VERSION 5.7 ;
  NOWIREEXTENSIONATPIN ON ;
  DIVIDERCHAR "/" ;
  BUSBITCHARS "[]" ;
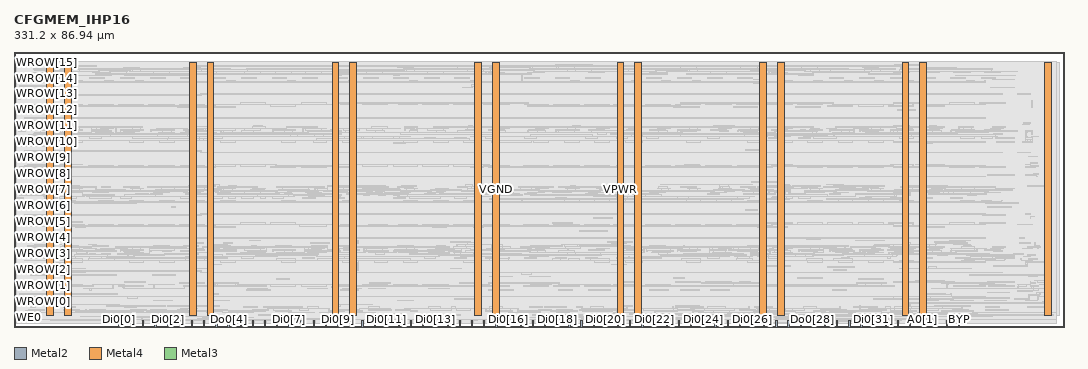
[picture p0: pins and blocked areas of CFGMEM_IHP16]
MACRO CFGMEM_IHP16
  CLASS BLOCK ;
  FOREIGN CFGMEM_IHP16 ;
  ORIGIN 0.000 0.000 ;
  SIZE 331.200 BY 86.940 ;
  PIN A0[0]
    DIRECTION INPUT ;
    USE SIGNAL ;
    ANTENNAGATEAREA 0.213200 ;
    ANTENNADIFFAREA 2.015400 ;
    PORT
      LAYER Metal2 ;
        RECT 282.520 0.000 282.920 2.000 ;
    END
  END A0[0]
  PIN A0[1]
    DIRECTION INPUT ;
    USE SIGNAL ;
    ANTENNAGATEAREA 0.213200 ;
    ANTENNADIFFAREA 2.015400 ;
    PORT
      LAYER Metal2 ;
        RECT 286.360 0.000 286.760 2.000 ;
    END
  END A0[1]
  PIN A0[2]
    DIRECTION INPUT ;
    USE SIGNAL ;
    ANTENNAGATEAREA 0.213200 ;
    ANTENNADIFFAREA 2.015400 ;
    PORT
      LAYER Metal2 ;
        RECT 290.200 0.000 290.600 2.000 ;
    END
  END A0[2]
  PIN A0[3]
    DIRECTION INPUT ;
    USE SIGNAL ;
    ANTENNAGATEAREA 0.213200 ;
    ANTENNADIFFAREA 2.015400 ;
    PORT
      LAYER Metal2 ;
        RECT 294.040 0.000 294.440 2.000 ;
    END
  END A0[3]
  PIN BYP
    DIRECTION INPUT ;
    USE SIGNAL ;
    ANTENNAGATEAREA 0.213200 ;
    ANTENNADIFFAREA 2.015400 ;
    PORT
      LAYER Metal2 ;
        RECT 297.880 0.000 298.280 2.000 ;
    END
  END BYP
  PIN Di0[0]
    DIRECTION INPUT ;
    USE SIGNAL ;
    ANTENNAGATEAREA 0.406900 ;
    ANTENNADIFFAREA 4.030800 ;
    PORT
      LAYER Metal2 ;
        RECT 32.920 0.000 33.320 2.000 ;
    END
  END Di0[0]
  PIN Di0[10]
    DIRECTION INPUT ;
    USE SIGNAL ;
    ANTENNAGATEAREA 0.406900 ;
    ANTENNADIFFAREA 4.030800 ;
    PORT
      LAYER Metal2 ;
        RECT 109.720 0.000 110.120 2.000 ;
    END
  END Di0[10]
  PIN Di0[11]
    DIRECTION INPUT ;
    USE SIGNAL ;
    ANTENNAGATEAREA 0.406900 ;
    ANTENNADIFFAREA 4.030800 ;
    PORT
      LAYER Metal2 ;
        RECT 117.400 0.000 117.800 2.000 ;
    END
  END Di0[11]
  PIN Di0[12]
    DIRECTION INPUT ;
    USE SIGNAL ;
    ANTENNAGATEAREA 0.406900 ;
    ANTENNADIFFAREA 4.030800 ;
    PORT
      LAYER Metal2 ;
        RECT 125.080 0.000 125.480 2.000 ;
    END
  END Di0[12]
  PIN Di0[13]
    DIRECTION INPUT ;
    USE SIGNAL ;
    ANTENNAGATEAREA 0.406900 ;
    ANTENNADIFFAREA 4.030800 ;
    PORT
      LAYER Metal2 ;
        RECT 132.760 0.000 133.160 2.000 ;
    END
  END Di0[13]
  PIN Di0[14]
    DIRECTION INPUT ;
    USE SIGNAL ;
    ANTENNAGATEAREA 0.406900 ;
    ANTENNADIFFAREA 4.030800 ;
    PORT
      LAYER Metal2 ;
        RECT 140.440 0.000 140.840 2.000 ;
    END
  END Di0[14]
  PIN Di0[15]
    DIRECTION INPUT ;
    USE SIGNAL ;
    ANTENNAGATEAREA 0.406900 ;
    ANTENNADIFFAREA 4.030800 ;
    PORT
      LAYER Metal2 ;
        RECT 148.120 0.000 148.520 2.000 ;
    END
  END Di0[15]
  PIN Di0[16]
    DIRECTION INPUT ;
    USE SIGNAL ;
    ANTENNAGATEAREA 0.406900 ;
    ANTENNADIFFAREA 4.030800 ;
    PORT
      LAYER Metal2 ;
        RECT 155.800 0.000 156.200 2.000 ;
    END
  END Di0[16]
  PIN Di0[17]
    DIRECTION INPUT ;
    USE SIGNAL ;
    ANTENNAGATEAREA 0.406900 ;
    ANTENNADIFFAREA 4.030800 ;
    PORT
      LAYER Metal2 ;
        RECT 163.480 0.000 163.880 2.000 ;
    END
  END Di0[17]
  PIN Di0[18]
    DIRECTION INPUT ;
    USE SIGNAL ;
    ANTENNAGATEAREA 0.406900 ;
    ANTENNADIFFAREA 4.030800 ;
    PORT
      LAYER Metal2 ;
        RECT 171.160 0.000 171.560 2.000 ;
    END
  END Di0[18]
  PIN Di0[19]
    DIRECTION INPUT ;
    USE SIGNAL ;
    ANTENNAGATEAREA 0.406900 ;
    ANTENNADIFFAREA 4.030800 ;
    PORT
      LAYER Metal2 ;
        RECT 178.840 0.000 179.240 2.000 ;
    END
  END Di0[19]
  PIN Di0[1]
    DIRECTION INPUT ;
    USE SIGNAL ;
    ANTENNAGATEAREA 0.406900 ;
    ANTENNADIFFAREA 4.030800 ;
    PORT
      LAYER Metal2 ;
        RECT 40.600 0.000 41.000 2.000 ;
    END
  END Di0[1]
  PIN Di0[20]
    DIRECTION INPUT ;
    USE SIGNAL ;
    ANTENNAGATEAREA 0.406900 ;
    ANTENNADIFFAREA 4.030800 ;
    PORT
      LAYER Metal2 ;
        RECT 186.520 0.000 186.920 2.000 ;
    END
  END Di0[20]
  PIN Di0[21]
    DIRECTION INPUT ;
    USE SIGNAL ;
    ANTENNAGATEAREA 0.406900 ;
    ANTENNADIFFAREA 4.030800 ;
    PORT
      LAYER Metal2 ;
        RECT 194.200 0.000 194.600 2.000 ;
    END
  END Di0[21]
  PIN Di0[22]
    DIRECTION INPUT ;
    USE SIGNAL ;
    ANTENNAGATEAREA 0.406900 ;
    ANTENNADIFFAREA 4.030800 ;
    PORT
      LAYER Metal2 ;
        RECT 201.880 0.000 202.280 2.000 ;
    END
  END Di0[22]
  PIN Di0[23]
    DIRECTION INPUT ;
    USE SIGNAL ;
    ANTENNAGATEAREA 0.406900 ;
    ANTENNADIFFAREA 4.030800 ;
    PORT
      LAYER Metal2 ;
        RECT 209.560 0.000 209.960 2.000 ;
    END
  END Di0[23]
  PIN Di0[24]
    DIRECTION INPUT ;
    USE SIGNAL ;
    ANTENNAGATEAREA 0.406900 ;
    ANTENNADIFFAREA 4.030800 ;
    PORT
      LAYER Metal2 ;
        RECT 217.240 0.000 217.640 2.000 ;
    END
  END Di0[24]
  PIN Di0[25]
    DIRECTION INPUT ;
    USE SIGNAL ;
    ANTENNAGATEAREA 0.406900 ;
    ANTENNADIFFAREA 4.030800 ;
    PORT
      LAYER Metal2 ;
        RECT 224.920 0.000 225.320 2.000 ;
    END
  END Di0[25]
  PIN Di0[26]
    DIRECTION INPUT ;
    USE SIGNAL ;
    ANTENNAGATEAREA 0.406900 ;
    ANTENNADIFFAREA 4.030800 ;
    PORT
      LAYER Metal2 ;
        RECT 232.600 0.000 233.000 2.000 ;
    END
  END Di0[26]
  PIN Di0[27]
    DIRECTION INPUT ;
    USE SIGNAL ;
    ANTENNAGATEAREA 0.406900 ;
    ANTENNADIFFAREA 4.030800 ;
    PORT
      LAYER Metal2 ;
        RECT 240.280 0.000 240.680 2.000 ;
    END
  END Di0[27]
  PIN Di0[28]
    DIRECTION INPUT ;
    USE SIGNAL ;
    ANTENNAGATEAREA 0.406900 ;
    ANTENNADIFFAREA 4.030800 ;
    PORT
      LAYER Metal2 ;
        RECT 247.960 0.000 248.360 2.000 ;
    END
  END Di0[28]
  PIN Di0[29]
    DIRECTION INPUT ;
    USE SIGNAL ;
    ANTENNAGATEAREA 0.406900 ;
    ANTENNADIFFAREA 4.030800 ;
    PORT
      LAYER Metal2 ;
        RECT 255.640 0.000 256.040 2.000 ;
    END
  END Di0[29]
  PIN Di0[2]
    DIRECTION INPUT ;
    USE SIGNAL ;
    ANTENNAGATEAREA 0.406900 ;
    ANTENNADIFFAREA 4.030800 ;
    PORT
      LAYER Metal2 ;
        RECT 48.280 0.000 48.680 2.000 ;
    END
  END Di0[2]
  PIN Di0[30]
    DIRECTION INPUT ;
    USE SIGNAL ;
    ANTENNAGATEAREA 0.406900 ;
    ANTENNADIFFAREA 4.030800 ;
    PORT
      LAYER Metal2 ;
        RECT 263.320 0.000 263.720 2.000 ;
    END
  END Di0[30]
  PIN Di0[31]
    DIRECTION INPUT ;
    USE SIGNAL ;
    ANTENNAGATEAREA 0.406900 ;
    ANTENNADIFFAREA 4.030800 ;
    PORT
      LAYER Metal2 ;
        RECT 271.000 0.000 271.400 2.000 ;
    END
  END Di0[31]
  PIN Di0[3]
    DIRECTION INPUT ;
    USE SIGNAL ;
    ANTENNAGATEAREA 0.406900 ;
    ANTENNADIFFAREA 4.030800 ;
    PORT
      LAYER Metal2 ;
        RECT 55.960 0.000 56.360 2.000 ;
    END
  END Di0[3]
  PIN Di0[4]
    DIRECTION INPUT ;
    USE SIGNAL ;
    ANTENNAGATEAREA 0.406900 ;
    ANTENNADIFFAREA 4.030800 ;
    PORT
      LAYER Metal2 ;
        RECT 63.640 0.000 64.040 2.000 ;
    END
  END Di0[4]
  PIN Di0[5]
    DIRECTION INPUT ;
    USE SIGNAL ;
    ANTENNAGATEAREA 0.406900 ;
    ANTENNADIFFAREA 4.030800 ;
    PORT
      LAYER Metal2 ;
        RECT 71.320 0.000 71.720 2.000 ;
    END
  END Di0[5]
  PIN Di0[6]
    DIRECTION INPUT ;
    USE SIGNAL ;
    ANTENNAGATEAREA 0.406900 ;
    ANTENNADIFFAREA 4.030800 ;
    PORT
      LAYER Metal2 ;
        RECT 79.000 0.000 79.400 2.000 ;
    END
  END Di0[6]
  PIN Di0[7]
    DIRECTION INPUT ;
    USE SIGNAL ;
    ANTENNAGATEAREA 0.406900 ;
    ANTENNADIFFAREA 4.030800 ;
    PORT
      LAYER Metal2 ;
        RECT 86.680 0.000 87.080 2.000 ;
    END
  END Di0[7]
  PIN Di0[8]
    DIRECTION INPUT ;
    USE SIGNAL ;
    ANTENNAGATEAREA 0.406900 ;
    ANTENNADIFFAREA 4.030800 ;
    PORT
      LAYER Metal2 ;
        RECT 94.360 0.000 94.760 2.000 ;
    END
  END Di0[8]
  PIN Di0[9]
    DIRECTION INPUT ;
    USE SIGNAL ;
    ANTENNAGATEAREA 0.406900 ;
    ANTENNADIFFAREA 4.030800 ;
    PORT
      LAYER Metal2 ;
        RECT 102.040 0.000 102.440 2.000 ;
    END
  END Di0[9]
  PIN Do0[0]
    DIRECTION OUTPUT ;
    USE SIGNAL ;
    ANTENNADIFFAREA 1.023000 ;
    PORT
      LAYER Metal2 ;
        RECT 36.760 0.000 37.160 2.000 ;
    END
  END Do0[0]
  PIN Do0[10]
    DIRECTION OUTPUT ;
    USE SIGNAL ;
    ANTENNADIFFAREA 1.023000 ;
    PORT
      LAYER Metal2 ;
        RECT 113.560 0.000 113.960 2.000 ;
    END
  END Do0[10]
  PIN Do0[11]
    DIRECTION OUTPUT ;
    USE SIGNAL ;
    ANTENNADIFFAREA 1.023000 ;
    PORT
      LAYER Metal2 ;
        RECT 121.240 0.000 121.640 2.000 ;
    END
  END Do0[11]
  PIN Do0[12]
    DIRECTION OUTPUT ;
    USE SIGNAL ;
    ANTENNADIFFAREA 1.023000 ;
    PORT
      LAYER Metal2 ;
        RECT 128.920 0.000 129.320 2.000 ;
    END
  END Do0[12]
  PIN Do0[13]
    DIRECTION OUTPUT ;
    USE SIGNAL ;
    ANTENNADIFFAREA 1.023000 ;
    PORT
      LAYER Metal2 ;
        RECT 136.600 0.000 137.000 2.000 ;
    END
  END Do0[13]
  PIN Do0[14]
    DIRECTION OUTPUT ;
    USE SIGNAL ;
    ANTENNADIFFAREA 1.023000 ;
    PORT
      LAYER Metal2 ;
        RECT 144.280 0.000 144.680 2.000 ;
    END
  END Do0[14]
  PIN Do0[15]
    DIRECTION OUTPUT ;
    USE SIGNAL ;
    ANTENNADIFFAREA 1.023000 ;
    PORT
      LAYER Metal2 ;
        RECT 151.960 0.000 152.360 2.000 ;
    END
  END Do0[15]
  PIN Do0[16]
    DIRECTION OUTPUT ;
    USE SIGNAL ;
    ANTENNADIFFAREA 1.023000 ;
    PORT
      LAYER Metal2 ;
        RECT 159.640 0.000 160.040 2.000 ;
    END
  END Do0[16]
  PIN Do0[17]
    DIRECTION OUTPUT ;
    USE SIGNAL ;
    ANTENNADIFFAREA 1.023000 ;
    PORT
      LAYER Metal2 ;
        RECT 167.320 0.000 167.720 2.000 ;
    END
  END Do0[17]
  PIN Do0[18]
    DIRECTION OUTPUT ;
    USE SIGNAL ;
    ANTENNADIFFAREA 1.023000 ;
    PORT
      LAYER Metal2 ;
        RECT 175.000 0.000 175.400 2.000 ;
    END
  END Do0[18]
  PIN Do0[19]
    DIRECTION OUTPUT ;
    USE SIGNAL ;
    ANTENNADIFFAREA 1.023000 ;
    PORT
      LAYER Metal2 ;
        RECT 182.680 0.000 183.080 2.000 ;
    END
  END Do0[19]
  PIN Do0[1]
    DIRECTION OUTPUT ;
    USE SIGNAL ;
    ANTENNADIFFAREA 1.023000 ;
    PORT
      LAYER Metal2 ;
        RECT 44.440 0.000 44.840 2.000 ;
    END
  END Do0[1]
  PIN Do0[20]
    DIRECTION OUTPUT ;
    USE SIGNAL ;
    ANTENNADIFFAREA 1.023000 ;
    PORT
      LAYER Metal2 ;
        RECT 190.360 0.000 190.760 2.000 ;
    END
  END Do0[20]
  PIN Do0[21]
    DIRECTION OUTPUT ;
    USE SIGNAL ;
    ANTENNADIFFAREA 1.023000 ;
    PORT
      LAYER Metal2 ;
        RECT 198.040 0.000 198.440 2.000 ;
    END
  END Do0[21]
  PIN Do0[22]
    DIRECTION OUTPUT ;
    USE SIGNAL ;
    ANTENNADIFFAREA 1.023000 ;
    PORT
      LAYER Metal2 ;
        RECT 205.720 0.000 206.120 2.000 ;
    END
  END Do0[22]
  PIN Do0[23]
    DIRECTION OUTPUT ;
    USE SIGNAL ;
    ANTENNADIFFAREA 1.023000 ;
    PORT
      LAYER Metal2 ;
        RECT 213.400 0.000 213.800 2.000 ;
    END
  END Do0[23]
  PIN Do0[24]
    DIRECTION OUTPUT ;
    USE SIGNAL ;
    ANTENNADIFFAREA 1.023000 ;
    PORT
      LAYER Metal2 ;
        RECT 221.080 0.000 221.480 2.000 ;
    END
  END Do0[24]
  PIN Do0[25]
    DIRECTION OUTPUT ;
    USE SIGNAL ;
    ANTENNADIFFAREA 1.023000 ;
    PORT
      LAYER Metal2 ;
        RECT 228.760 0.000 229.160 2.000 ;
    END
  END Do0[25]
  PIN Do0[26]
    DIRECTION OUTPUT ;
    USE SIGNAL ;
    ANTENNADIFFAREA 1.023000 ;
    PORT
      LAYER Metal2 ;
        RECT 236.440 0.000 236.840 2.000 ;
    END
  END Do0[26]
  PIN Do0[27]
    DIRECTION OUTPUT ;
    USE SIGNAL ;
    ANTENNADIFFAREA 1.023000 ;
    PORT
      LAYER Metal2 ;
        RECT 244.120 0.000 244.520 2.000 ;
    END
  END Do0[27]
  PIN Do0[28]
    DIRECTION OUTPUT ;
    USE SIGNAL ;
    ANTENNADIFFAREA 1.023000 ;
    PORT
      LAYER Metal2 ;
        RECT 251.800 0.000 252.200 2.000 ;
    END
  END Do0[28]
  PIN Do0[29]
    DIRECTION OUTPUT ;
    USE SIGNAL ;
    ANTENNADIFFAREA 1.023000 ;
    PORT
      LAYER Metal2 ;
        RECT 259.480 0.000 259.880 2.000 ;
    END
  END Do0[29]
  PIN Do0[2]
    DIRECTION OUTPUT ;
    USE SIGNAL ;
    ANTENNADIFFAREA 1.023000 ;
    PORT
      LAYER Metal2 ;
        RECT 52.120 0.000 52.520 2.000 ;
    END
  END Do0[2]
  PIN Do0[30]
    DIRECTION OUTPUT ;
    USE SIGNAL ;
    ANTENNADIFFAREA 1.023000 ;
    PORT
      LAYER Metal2 ;
        RECT 267.160 0.000 267.560 2.000 ;
    END
  END Do0[30]
  PIN Do0[31]
    DIRECTION OUTPUT ;
    USE SIGNAL ;
    ANTENNADIFFAREA 1.023000 ;
    PORT
      LAYER Metal2 ;
        RECT 274.840 0.000 275.240 2.000 ;
    END
  END Do0[31]
  PIN Do0[3]
    DIRECTION OUTPUT ;
    USE SIGNAL ;
    ANTENNADIFFAREA 1.023000 ;
    PORT
      LAYER Metal2 ;
        RECT 59.800 0.000 60.200 2.000 ;
    END
  END Do0[3]
  PIN Do0[4]
    DIRECTION OUTPUT ;
    USE SIGNAL ;
    ANTENNADIFFAREA 1.023000 ;
    PORT
      LAYER Metal2 ;
        RECT 67.480 0.000 67.880 2.000 ;
    END
  END Do0[4]
  PIN Do0[5]
    DIRECTION OUTPUT ;
    USE SIGNAL ;
    ANTENNADIFFAREA 1.023000 ;
    PORT
      LAYER Metal2 ;
        RECT 75.160 0.000 75.560 2.000 ;
    END
  END Do0[5]
  PIN Do0[6]
    DIRECTION OUTPUT ;
    USE SIGNAL ;
    ANTENNADIFFAREA 1.023000 ;
    PORT
      LAYER Metal2 ;
        RECT 82.840 0.000 83.240 2.000 ;
    END
  END Do0[6]
  PIN Do0[7]
    DIRECTION OUTPUT ;
    USE SIGNAL ;
    ANTENNADIFFAREA 1.023000 ;
    PORT
      LAYER Metal2 ;
        RECT 90.520 0.000 90.920 2.000 ;
    END
  END Do0[7]
  PIN Do0[8]
    DIRECTION OUTPUT ;
    USE SIGNAL ;
    ANTENNADIFFAREA 1.023000 ;
    PORT
      LAYER Metal2 ;
        RECT 98.200 0.000 98.600 2.000 ;
    END
  END Do0[8]
  PIN Do0[9]
    DIRECTION OUTPUT ;
    USE SIGNAL ;
    ANTENNADIFFAREA 1.023000 ;
    PORT
      LAYER Metal2 ;
        RECT 105.880 0.000 106.280 2.000 ;
    END
  END Do0[9]
  PIN EN0
    DIRECTION INPUT ;
    USE SIGNAL ;
    ANTENNAGATEAREA 0.373100 ;
    ANTENNADIFFAREA 4.030800 ;
    PORT
      LAYER Metal2 ;
        RECT 278.680 0.000 279.080 2.000 ;
    END
  END EN0
  PIN VGND
    DIRECTION INOUT ;
    USE GROUND ;
    PORT
      LAYER Metal4 ;
        RECT 16.010 3.560 18.110 83.380 ;
    END
    PORT
      LAYER Metal4 ;
        RECT 60.970 3.560 63.070 83.380 ;
    END
    PORT
      LAYER Metal4 ;
        RECT 105.930 3.560 108.030 83.380 ;
    END
    PORT
      LAYER Metal4 ;
        RECT 150.890 3.560 152.990 83.380 ;
    END
    PORT
      LAYER Metal4 ;
        RECT 195.850 3.560 197.950 83.380 ;
    END
    PORT
      LAYER Metal4 ;
        RECT 240.810 3.560 242.910 83.380 ;
    END
    PORT
      LAYER Metal4 ;
        RECT 285.770 3.560 287.870 83.380 ;
    END
  END VGND
  PIN VPWR
    DIRECTION INOUT ;
    USE POWER ;
    PORT
      LAYER Metal4 ;
        RECT 10.390 3.560 12.490 83.380 ;
    END
    PORT
      LAYER Metal4 ;
        RECT 55.350 3.560 57.450 83.380 ;
    END
    PORT
      LAYER Metal4 ;
        RECT 100.310 3.560 102.410 83.380 ;
    END
    PORT
      LAYER Metal4 ;
        RECT 145.270 3.560 147.370 83.380 ;
    END
    PORT
      LAYER Metal4 ;
        RECT 190.230 3.560 192.330 83.380 ;
    END
    PORT
      LAYER Metal4 ;
        RECT 235.190 3.560 237.290 83.380 ;
    END
    PORT
      LAYER Metal4 ;
        RECT 280.150 3.560 282.250 83.380 ;
    END
    PORT
      LAYER Metal4 ;
        RECT 325.110 3.560 327.210 83.380 ;
    END
  END VPWR
  PIN WE0
    DIRECTION INPUT ;
    USE SIGNAL ;
    ANTENNAGATEAREA 3.078400 ;
    ANTENNADIFFAREA 32.246399 ;
    PORT
      LAYER Metal3 ;
        RECT 0.000 2.740 2.000 3.140 ;
    END
  END WE0
  PIN WROW[0]
    DIRECTION INPUT ;
    USE SIGNAL ;
    ANTENNAGATEAREA 0.192400 ;
    ANTENNADIFFAREA 2.015400 ;
    PORT
      LAYER Metal3 ;
        RECT 0.000 7.780 2.000 8.180 ;
    END
  END WROW[0]
  PIN WROW[10]
    DIRECTION INPUT ;
    USE SIGNAL ;
    ANTENNAGATEAREA 0.192400 ;
    ANTENNADIFFAREA 2.015400 ;
    PORT
      LAYER Metal3 ;
        RECT 0.000 58.180 2.000 58.580 ;
    END
  END WROW[10]
  PIN WROW[11]
    DIRECTION INPUT ;
    USE SIGNAL ;
    ANTENNAGATEAREA 0.192400 ;
    ANTENNADIFFAREA 2.015400 ;
    PORT
      LAYER Metal3 ;
        RECT 0.000 63.220 2.000 63.620 ;
    END
  END WROW[11]
  PIN WROW[12]
    DIRECTION INPUT ;
    USE SIGNAL ;
    ANTENNAGATEAREA 0.192400 ;
    ANTENNADIFFAREA 2.015400 ;
    PORT
      LAYER Metal3 ;
        RECT 0.000 68.260 2.000 68.660 ;
    END
  END WROW[12]
  PIN WROW[13]
    DIRECTION INPUT ;
    USE SIGNAL ;
    ANTENNAGATEAREA 0.192400 ;
    ANTENNADIFFAREA 2.015400 ;
    PORT
      LAYER Metal3 ;
        RECT 0.000 73.300 2.000 73.700 ;
    END
  END WROW[13]
  PIN WROW[14]
    DIRECTION INPUT ;
    USE SIGNAL ;
    ANTENNAGATEAREA 0.192400 ;
    ANTENNADIFFAREA 2.015400 ;
    PORT
      LAYER Metal3 ;
        RECT 0.000 78.340 2.000 78.740 ;
    END
  END WROW[14]
  PIN WROW[15]
    DIRECTION INPUT ;
    USE SIGNAL ;
    ANTENNAGATEAREA 0.192400 ;
    ANTENNADIFFAREA 2.015400 ;
    PORT
      LAYER Metal3 ;
        RECT 0.000 83.380 2.000 83.780 ;
    END
  END WROW[15]
  PIN WROW[1]
    DIRECTION INPUT ;
    USE SIGNAL ;
    ANTENNAGATEAREA 0.192400 ;
    ANTENNADIFFAREA 2.015400 ;
    PORT
      LAYER Metal3 ;
        RECT 0.000 12.820 2.000 13.220 ;
    END
  END WROW[1]
  PIN WROW[2]
    DIRECTION INPUT ;
    USE SIGNAL ;
    ANTENNAGATEAREA 0.192400 ;
    ANTENNADIFFAREA 2.015400 ;
    PORT
      LAYER Metal3 ;
        RECT 0.000 17.860 2.000 18.260 ;
    END
  END WROW[2]
  PIN WROW[3]
    DIRECTION INPUT ;
    USE SIGNAL ;
    ANTENNAGATEAREA 0.192400 ;
    ANTENNADIFFAREA 2.015400 ;
    PORT
      LAYER Metal3 ;
        RECT 0.000 22.900 2.000 23.300 ;
    END
  END WROW[3]
  PIN WROW[4]
    DIRECTION INPUT ;
    USE SIGNAL ;
    ANTENNAGATEAREA 0.192400 ;
    ANTENNADIFFAREA 2.015400 ;
    PORT
      LAYER Metal3 ;
        RECT 0.000 27.940 2.000 28.340 ;
    END
  END WROW[4]
  PIN WROW[5]
    DIRECTION INPUT ;
    USE SIGNAL ;
    ANTENNAGATEAREA 0.192400 ;
    ANTENNADIFFAREA 2.015400 ;
    PORT
      LAYER Metal3 ;
        RECT 0.000 32.980 2.000 33.380 ;
    END
  END WROW[5]
  PIN WROW[6]
    DIRECTION INPUT ;
    USE SIGNAL ;
    ANTENNAGATEAREA 0.192400 ;
    ANTENNADIFFAREA 2.015400 ;
    PORT
      LAYER Metal3 ;
        RECT 0.000 38.020 2.000 38.420 ;
    END
  END WROW[6]
  PIN WROW[7]
    DIRECTION INPUT ;
    USE SIGNAL ;
    ANTENNAGATEAREA 0.192400 ;
    ANTENNADIFFAREA 2.015400 ;
    PORT
      LAYER Metal3 ;
        RECT 0.000 43.060 2.000 43.460 ;
    END
  END WROW[7]
  PIN WROW[8]
    DIRECTION INPUT ;
    USE SIGNAL ;
    ANTENNAGATEAREA 0.192400 ;
    ANTENNADIFFAREA 2.015400 ;
    PORT
      LAYER Metal3 ;
        RECT 0.000 48.100 2.000 48.500 ;
    END
  END WROW[8]
  PIN WROW[9]
    DIRECTION INPUT ;
    USE SIGNAL ;
    ANTENNAGATEAREA 0.192400 ;
    ANTENNADIFFAREA 2.015400 ;
    PORT
      LAYER Metal3 ;
        RECT 0.000 53.140 2.000 53.540 ;
    END
  END WROW[9]
  OBS
      LAYER GatPoly ;
        RECT 1.440 3.630 329.760 83.310 ;
      LAYER Metal1 ;
        RECT 1.440 3.560 329.760 83.380 ;
      LAYER Metal2 ;
        RECT 0.855 2.210 328.905 83.725 ;
        RECT 0.855 1.115 32.710 2.210 ;
        RECT 33.530 1.115 36.550 2.210 ;
        RECT 37.370 1.115 40.390 2.210 ;
        RECT 41.210 1.115 44.230 2.210 ;
        RECT 45.050 1.115 48.070 2.210 ;
        RECT 48.890 1.115 51.910 2.210 ;
        RECT 52.730 1.115 55.750 2.210 ;
        RECT 56.570 1.115 59.590 2.210 ;
        RECT 60.410 1.115 63.430 2.210 ;
        RECT 64.250 1.115 67.270 2.210 ;
        RECT 68.090 1.115 71.110 2.210 ;
        RECT 71.930 1.115 74.950 2.210 ;
        RECT 75.770 1.115 78.790 2.210 ;
        RECT 79.610 1.115 82.630 2.210 ;
        RECT 83.450 1.115 86.470 2.210 ;
        RECT 87.290 1.115 90.310 2.210 ;
        RECT 91.130 1.115 94.150 2.210 ;
        RECT 94.970 1.115 97.990 2.210 ;
        RECT 98.810 1.115 101.830 2.210 ;
        RECT 102.650 1.115 105.670 2.210 ;
        RECT 106.490 1.115 109.510 2.210 ;
        RECT 110.330 1.115 113.350 2.210 ;
        RECT 114.170 1.115 117.190 2.210 ;
        RECT 118.010 1.115 121.030 2.210 ;
        RECT 121.850 1.115 124.870 2.210 ;
        RECT 125.690 1.115 128.710 2.210 ;
        RECT 129.530 1.115 132.550 2.210 ;
        RECT 133.370 1.115 136.390 2.210 ;
        RECT 137.210 1.115 140.230 2.210 ;
        RECT 141.050 1.115 144.070 2.210 ;
        RECT 144.890 1.115 147.910 2.210 ;
        RECT 148.730 1.115 151.750 2.210 ;
        RECT 152.570 1.115 155.590 2.210 ;
        RECT 156.410 1.115 159.430 2.210 ;
        RECT 160.250 1.115 163.270 2.210 ;
        RECT 164.090 1.115 167.110 2.210 ;
        RECT 167.930 1.115 170.950 2.210 ;
        RECT 171.770 1.115 174.790 2.210 ;
        RECT 175.610 1.115 178.630 2.210 ;
        RECT 179.450 1.115 182.470 2.210 ;
        RECT 183.290 1.115 186.310 2.210 ;
        RECT 187.130 1.115 190.150 2.210 ;
        RECT 190.970 1.115 193.990 2.210 ;
        RECT 194.810 1.115 197.830 2.210 ;
        RECT 198.650 1.115 201.670 2.210 ;
        RECT 202.490 1.115 205.510 2.210 ;
        RECT 206.330 1.115 209.350 2.210 ;
        RECT 210.170 1.115 213.190 2.210 ;
        RECT 214.010 1.115 217.030 2.210 ;
        RECT 217.850 1.115 220.870 2.210 ;
        RECT 221.690 1.115 224.710 2.210 ;
        RECT 225.530 1.115 228.550 2.210 ;
        RECT 229.370 1.115 232.390 2.210 ;
        RECT 233.210 1.115 236.230 2.210 ;
        RECT 237.050 1.115 240.070 2.210 ;
        RECT 240.890 1.115 243.910 2.210 ;
        RECT 244.730 1.115 247.750 2.210 ;
        RECT 248.570 1.115 251.590 2.210 ;
        RECT 252.410 1.115 255.430 2.210 ;
        RECT 256.250 1.115 259.270 2.210 ;
        RECT 260.090 1.115 263.110 2.210 ;
        RECT 263.930 1.115 266.950 2.210 ;
        RECT 267.770 1.115 270.790 2.210 ;
        RECT 271.610 1.115 274.630 2.210 ;
        RECT 275.450 1.115 278.470 2.210 ;
        RECT 279.290 1.115 282.310 2.210 ;
        RECT 283.130 1.115 286.150 2.210 ;
        RECT 286.970 1.115 289.990 2.210 ;
        RECT 290.810 1.115 293.830 2.210 ;
        RECT 294.650 1.115 297.670 2.210 ;
        RECT 298.490 1.115 328.905 2.210 ;
     LAYER Metal3 ;
        RECT 159.695 2.840 164.785 3.040 ;
        RECT 155.855 4.520 166.180 4.720 ;
        RECT 155.855 4.720 157.105 4.940 ;
        RECT 158.735 4.720 166.180 4.940 ;
        RECT 171.215 4.520 175.345 4.940 ;
        RECT 148.700 4.940 157.105 5.140 ;
        RECT 158.735 4.940 166.225 5.140 ;
        RECT 169.340 4.940 177.745 5.140 ;
        RECT 148.700 5.140 148.945 5.360 ;
        RECT 165.500 5.140 166.225 5.360 ;
        RECT 169.340 5.140 169.585 5.360 ;
        RECT 120.335 5.360 124.945 5.560 ;
        RECT 165.500 5.360 169.585 5.560 ;
        RECT 171.215 5.140 176.305 5.560 ;
        RECT 123.215 5.560 124.945 5.780 ;
        RECT 131.375 5.360 137.905 5.780 ;
        RECT 139.535 5.360 144.145 5.780 ;
        RECT 148.655 5.360 148.945 5.780 ;
        RECT 150.095 5.140 156.625 5.780 ;
        RECT 158.780 5.140 158.980 5.780 ;
        RECT 123.215 5.780 158.980 5.980 ;
        RECT 130.895 5.980 134.545 6.400 ;
        RECT 138.095 5.980 139.345 6.400 ;
        RECT 150.095 5.980 154.225 6.400 ;
        RECT 162.575 6.200 166.705 6.400 ;
        RECT 232.700 1.160 255.025 1.360 ;
        RECT 248.060 1.360 255.025 1.580 ;
        RECT 248.060 1.580 274.225 1.780 ;
        RECT 232.700 1.360 232.900 2.000 ;
        RECT 248.060 1.780 248.305 2.000 ;
        RECT 251.855 1.780 274.225 2.000 ;
        RECT 232.655 2.000 232.945 2.200 ;
        RECT 186.575 2.000 198.820 2.200 ;
        RECT 186.575 2.200 189.265 2.420 ;
        RECT 198.575 2.200 198.820 2.420 ;
        RECT 248.015 2.000 248.305 2.420 ;
        RECT 251.855 2.000 279.985 2.420 ;
        RECT 178.895 2.420 189.265 2.620 ;
        RECT 205.775 2.420 222.385 2.620 ;
        RECT 240.335 2.420 289.585 2.620 ;
        RECT 178.895 2.620 183.985 2.840 ;
        RECT 198.575 2.420 198.865 2.840 ;
        RECT 205.775 2.620 212.785 2.840 ;
        RECT 240.335 2.620 251.185 2.840 ;
        RECT 175.055 2.840 183.985 3.040 ;
        RECT 198.095 2.840 212.785 3.040 ;
        RECT 251.900 2.620 254.545 3.040 ;
        RECT 175.055 3.040 179.665 3.260 ;
        RECT 198.095 3.040 203.185 3.260 ;
        RECT 228.815 2.840 251.185 3.260 ;
        RECT 251.900 3.040 252.100 3.260 ;
        RECT 259.100 2.620 265.105 3.260 ;
        RECT 267.215 2.620 269.905 3.260 ;
        RECT 171.215 3.260 179.665 3.460 ;
        RECT 190.415 3.260 203.185 3.460 ;
        RECT 217.295 3.260 252.100 3.460 ;
        RECT 255.695 3.260 308.785 3.460 ;
        RECT 171.215 3.460 179.185 3.680 ;
        RECT 199.535 3.460 203.185 3.680 ;
        RECT 217.295 3.460 233.425 3.680 ;
        RECT 244.175 3.460 252.100 3.680 ;
        RECT 255.695 3.460 270.385 3.680 ;
        RECT 297.935 3.460 308.785 3.680 ;
        RECT 163.535 3.680 179.185 3.880 ;
        RECT 297.935 3.680 327.985 3.880 ;
        RECT 209.615 3.680 233.425 3.880 ;
        RECT 244.175 3.680 270.385 3.880 ;
        RECT 195.935 3.460 197.865 4.100 ;
        RECT 199.535 3.680 205.105 4.100 ;
        RECT 209.615 3.880 214.180 4.100 ;
        RECT 224.975 3.880 233.425 4.100 ;
        RECT 235.055 3.460 235.345 4.100 ;
        RECT 240.895 3.460 242.825 4.100 ;
        RECT 244.175 3.880 246.865 4.100 ;
        RECT 263.375 3.880 270.385 4.100 ;
        RECT 274.460 3.460 285.265 4.100 ;
        RECT 285.855 3.460 287.785 4.100 ;
        RECT 297.935 3.880 303.985 4.100 ;
        RECT 187.535 4.100 192.145 4.300 ;
        RECT 194.255 4.100 214.180 4.300 ;
        RECT 224.975 4.100 246.865 4.300 ;
        RECT 263.375 4.100 303.985 4.300 ;
        RECT 188.975 4.300 192.145 4.520 ;
        RECT 194.255 4.300 198.385 4.520 ;
        RECT 224.975 4.300 241.585 4.520 ;
        RECT 246.620 4.300 246.865 4.520 ;
        RECT 263.375 4.300 265.585 4.520 ;
        RECT 302.255 4.300 303.985 4.520 ;
        RECT 188.975 4.520 198.385 4.720 ;
        RECT 201.935 4.300 202.225 4.720 ;
        RECT 246.620 4.520 252.580 4.720 ;
        RECT 284.975 4.300 294.385 4.720 ;
        RECT 302.255 4.520 328.945 4.720 ;
        RECT 215.855 4.520 241.585 4.720 ;
        RECT 254.735 4.520 265.585 4.720 ;
        RECT 273.500 4.300 283.345 4.720 ;
        RECT 201.980 4.720 202.225 4.940 ;
        RECT 213.980 4.300 214.180 4.940 ;
        RECT 215.855 4.720 217.585 4.940 ;
        RECT 233.135 4.720 241.585 4.940 ;
        RECT 252.335 4.720 252.580 4.940 ;
        RECT 254.735 4.720 255.985 4.940 ;
        RECT 257.180 4.720 265.585 4.940 ;
        RECT 273.500 4.720 273.745 4.940 ;
        RECT 276.380 4.720 283.345 4.940 ;
        RECT 292.655 4.720 294.385 4.940 ;
        RECT 302.255 4.720 302.500 4.940 ;
        RECT 213.935 4.940 217.585 5.140 ;
        RECT 252.335 4.940 255.985 5.140 ;
        RECT 276.380 4.940 284.785 5.140 ;
        RECT 292.655 4.940 302.500 5.140 ;
        RECT 189.980 4.720 196.900 5.140 ;
        RECT 201.980 4.940 209.380 5.140 ;
        RECT 233.135 4.940 246.385 5.140 ;
        RECT 257.180 4.940 273.745 5.140 ;
        RECT 179.375 4.940 188.785 5.360 ;
        RECT 189.980 5.140 195.505 5.360 ;
        RECT 196.655 5.140 196.900 5.360 ;
        RECT 201.980 5.140 207.985 5.360 ;
        RECT 209.180 5.140 209.380 5.360 ;
        RECT 213.935 5.140 214.705 5.360 ;
        RECT 220.700 4.720 225.745 5.360 ;
        RECT 233.135 5.140 233.905 5.360 ;
        RECT 245.615 5.140 246.385 5.360 ;
        RECT 254.255 5.140 255.985 5.360 ;
        RECT 257.180 5.140 262.705 5.360 ;
        RECT 266.780 5.140 273.745 5.360 ;
        RECT 276.380 5.140 276.625 5.360 ;
        RECT 178.415 5.360 195.505 5.560 ;
        RECT 196.655 5.360 196.945 5.560 ;
        RECT 228.815 5.360 233.905 5.560 ;
        RECT 254.255 5.360 262.705 5.560 ;
        RECT 296.015 5.140 301.105 5.560 ;
        RECT 209.180 5.360 214.705 5.560 ;
        RECT 234.575 5.140 237.220 5.560 ;
        RECT 266.780 5.360 275.185 5.560 ;
        RECT 196.700 5.560 196.945 5.780 ;
        RECT 198.575 5.360 207.985 5.780 ;
        RECT 209.180 5.560 209.380 5.780 ;
        RECT 213.455 5.560 214.705 5.780 ;
        RECT 217.775 5.360 227.185 5.780 ;
        RECT 228.815 5.560 231.940 5.780 ;
        RECT 234.575 5.560 235.345 5.780 ;
        RECT 236.975 5.560 237.220 5.780 ;
        RECT 238.415 5.140 243.505 5.780 ;
        RECT 245.615 5.360 249.265 5.780 ;
        RECT 254.255 5.560 260.740 5.780 ;
        RECT 269.615 5.560 275.185 5.780 ;
        RECT 276.335 5.360 276.625 5.780 ;
        RECT 277.775 5.140 282.865 5.780 ;
        RECT 286.415 5.360 291.505 5.780 ;
        RECT 296.015 5.560 299.140 5.780 ;
        RECT 196.700 5.780 209.380 5.980 ;
        RECT 178.940 5.560 193.540 5.980 ;
        RECT 213.455 5.780 231.940 5.980 ;
        RECT 236.975 5.780 260.740 5.980 ;
        RECT 269.615 5.780 299.140 5.980 ;
        RECT 178.940 5.980 179.185 6.200 ;
        RECT 193.295 5.980 193.540 6.200 ;
        RECT 208.700 5.980 209.380 6.200 ;
        RECT 213.455 5.980 217.585 6.200 ;
        RECT 231.695 5.980 231.940 6.200 ;
        RECT 234.095 5.780 235.345 6.200 ;
        RECT 236.975 5.980 239.185 6.200 ;
        RECT 260.495 5.980 260.740 6.200 ;
        RECT 266.780 5.560 266.980 6.200 ;
        RECT 269.615 5.980 272.305 6.200 ;
        RECT 298.895 5.980 299.140 6.200 ;
        RECT 177.455 6.200 179.185 6.400 ;
        RECT 181.775 5.980 185.905 6.400 ;
        RECT 207.695 5.980 207.985 6.400 ;
        RECT 208.700 6.200 217.585 6.400 ;
        RECT 218.735 5.980 224.305 6.400 ;
        RECT 231.695 6.200 231.985 6.400 ;
        RECT 233.615 6.200 239.185 6.400 ;
        RECT 248.975 5.980 253.105 6.400 ;
        RECT 260.495 6.200 260.785 6.400 ;
        RECT 264.815 6.200 272.305 6.400 ;
        RECT 274.895 5.980 276.625 6.400 ;
        RECT 277.775 5.980 281.905 6.400 ;
        RECT 283.055 5.980 292.945 6.400 ;
        RECT 193.295 6.200 193.585 6.620 ;
        RECT 290.255 6.400 292.945 6.620 ;
        RECT 298.895 6.200 299.185 6.620 ;
        RECT 190.895 6.620 195.025 6.820 ;
        RECT 208.700 6.400 216.145 6.820 ;
        RECT 266.735 6.400 267.025 6.820 ;
        RECT 290.255 6.620 301.585 6.820 ;
        RECT 295.535 8.300 302.545 8.500 ;
        RECT 287.855 8.300 291.505 8.720 ;
        RECT 295.535 8.500 296.260 8.720 ;
        RECT 271.055 8.720 296.260 8.920 ;
        RECT 296.060 8.920 296.260 9.140 ;
        RECT 296.060 9.140 314.065 9.340 ;
        RECT 35.855 9.140 39.025 9.560 ;
        RECT 277.295 8.920 289.105 9.560 ;
        RECT 296.060 9.340 306.385 9.560 ;
        RECT 3.215 9.560 306.385 9.760 ;
        RECT 286.895 9.760 295.780 10.180 ;
        RECT 286.895 10.180 293.905 10.400 ;
        RECT 295.535 10.180 295.780 10.400 ;
        RECT 286.415 10.400 293.905 10.600 ;
        RECT 295.535 10.400 295.825 10.600 ;
        RECT 23.855 11.660 24.300 12.080 ;
        RECT 1.775 12.080 2.500 12.280 ;
        RECT 4.175 12.080 12.100 12.280 ;
        RECT 21.935 12.080 31.300 12.280 ;
        RECT 34.460 12.080 53.860 12.280 ;
        RECT 34.460 12.280 34.705 12.500 ;
        RECT 100.175 12.500 101.425 12.700 ;
        RECT 2.300 12.280 2.500 12.820 ;
        RECT 2.000 12.820 2.500 12.920 ;
        RECT 11.900 12.280 12.100 12.920 ;
        RECT 31.100 12.280 31.300 12.920 ;
        RECT 34.260 12.500 34.705 12.920 ;
        RECT 44.060 12.280 44.260 12.920 ;
        RECT 53.660 12.280 53.860 12.920 ;
        RECT 56.540 12.500 57.220 12.920 ;
        RECT 100.700 12.700 101.425 12.920 ;
        RECT 32.975 12.920 40.945 13.120 ;
        RECT 53.615 12.920 79.780 13.120 ;
        RECT 100.700 12.920 156.145 13.120 ;
        RECT 160.655 12.920 168.625 13.120 ;
        RECT 170.255 12.920 178.225 13.120 ;
        RECT 179.855 12.920 277.585 13.120 ;
        RECT 2.000 12.920 5.425 13.120 ;
        RECT 11.855 12.920 25.105 13.120 ;
        RECT 3.215 13.120 5.425 13.340 ;
        RECT 11.855 13.120 12.580 13.340 ;
        RECT 24.860 13.120 25.105 13.340 ;
        RECT 31.055 12.920 31.345 13.340 ;
        RECT 32.975 13.120 34.705 13.340 ;
        RECT 44.015 12.920 44.305 13.340 ;
        RECT 70.460 13.120 79.780 13.340 ;
        RECT 80.975 12.920 88.945 13.340 ;
        RECT 90.575 12.920 98.545 13.340 ;
        RECT 100.700 13.120 108.145 13.340 ;
        RECT 163.055 13.120 168.625 13.340 ;
        RECT 171.695 13.120 178.225 13.340 ;
        RECT 179.855 13.120 188.260 13.340 ;
        RECT 3.215 13.340 12.580 13.540 ;
        RECT 13.775 13.120 21.745 13.540 ;
        RECT 24.860 13.340 34.705 13.540 ;
        RECT 42.575 13.340 50.545 13.540 ;
        RECT 70.460 13.340 108.145 13.540 ;
        RECT 109.775 13.120 117.745 13.540 ;
        RECT 119.855 13.120 127.345 13.540 ;
        RECT 128.975 13.120 136.945 13.540 ;
        RECT 147.740 13.120 149.860 13.540 ;
        RECT 171.695 13.340 188.260 13.540 ;
        RECT 188.975 13.120 197.425 13.540 ;
        RECT 199.055 13.120 207.025 13.540 ;
        RECT 236.975 13.120 266.065 13.540 ;
        RECT 63.260 13.120 63.460 13.760 ;
        RECT 64.175 13.120 69.745 13.760 ;
        RECT 70.460 13.540 70.660 13.760 ;
        RECT 112.175 13.540 117.745 13.760 ;
        RECT 149.615 13.540 149.860 13.760 ;
        RECT 163.055 13.340 169.585 13.760 ;
        RECT 171.695 13.540 171.940 13.760 ;
        RECT 226.895 13.120 235.825 13.760 ;
        RECT 236.975 13.540 237.220 13.760 ;
        RECT 265.820 13.540 266.065 13.760 ;
        RECT 268.655 13.120 273.745 13.760 ;
        RECT 63.215 13.760 70.660 13.960 ;
        RECT 112.175 13.760 118.705 13.960 ;
        RECT 149.615 13.760 171.940 13.960 ;
        RECT 216.815 13.760 237.220 13.960 ;
        RECT 265.820 13.760 275.185 13.960 ;
        RECT 218.255 13.960 226.225 14.380 ;
        RECT 228.815 13.960 232.465 14.380 ;
        RECT 162.575 15.860 169.105 16.060 ;
        RECT 160.175 16.700 163.345 17.120 ;
        RECT 2.255 17.120 22.705 17.320 ;
        RECT 58.895 17.120 311.665 17.320 ;
        RECT 3.215 17.320 22.705 17.540 ;
        RECT 58.895 17.320 59.140 17.540 ;
        RECT 3.215 17.540 59.140 17.740 ;
        RECT 3.215 17.740 4.900 17.960 ;
        RECT 2.000 17.960 4.900 18.160 ;
        RECT 4.700 18.160 4.900 18.380 ;
        RECT 4.700 18.380 22.705 18.580 ;
        RECT 16.095 18.580 18.025 19.000 ;
        RECT 107.855 17.960 108.580 18.160 ;
        RECT 108.380 18.160 108.580 18.800 ;
        RECT 106.015 18.800 108.580 19.000 ;
        RECT 108.380 19.000 108.580 20.480 ;
        RECT 277.295 20.480 306.385 20.680 ;
        RECT 17.135 20.480 21.745 20.900 ;
        RECT 36.335 20.480 40.945 20.900 ;
        RECT 45.935 20.480 50.545 20.900 ;
        RECT 65.135 20.480 69.745 20.900 ;
        RECT 84.335 20.480 88.945 20.900 ;
        RECT 103.535 20.480 108.580 20.900 ;
        RECT 113.615 20.480 117.745 20.900 ;
        RECT 122.735 20.480 127.345 20.900 ;
        RECT 141.935 20.480 146.545 20.900 ;
        RECT 183.215 20.480 187.825 20.900 ;
        RECT 192.815 20.480 198.385 20.900 ;
        RECT 212.015 20.480 216.625 20.900 ;
        RECT 231.215 20.480 235.825 20.900 ;
        RECT 250.415 20.480 255.025 20.900 ;
        RECT 260.015 20.480 264.625 20.900 ;
        RECT 269.615 20.480 274.225 20.900 ;
        RECT 277.295 20.680 277.540 20.900 ;
        RECT 3.215 20.900 277.540 21.100 ;
        RECT 279.215 20.680 283.825 21.100 ;
        RECT 298.895 20.680 303.025 21.100 ;
        RECT 306.575 20.900 312.580 21.100 ;
        RECT 299.855 21.100 303.025 21.320 ;
        RECT 306.575 21.100 309.700 21.320 ;
        RECT 312.335 21.100 312.580 21.320 ;
        RECT 15.695 21.100 21.745 21.520 ;
        RECT 23.375 21.100 31.825 21.520 ;
        RECT 82.895 21.100 88.945 21.520 ;
        RECT 95.855 21.100 124.945 21.520 ;
        RECT 169.775 21.100 172.465 21.520 ;
        RECT 175.055 21.100 178.225 21.520 ;
        RECT 181.775 21.100 187.825 21.520 ;
        RECT 210.575 21.100 216.625 21.520 ;
        RECT 227.855 21.100 232.945 21.520 ;
        RECT 249.935 21.100 255.025 21.520 ;
        RECT 258.575 21.100 264.625 21.520 ;
        RECT 150.095 21.100 156.100 21.520 ;
        RECT 299.855 21.320 309.700 21.520 ;
        RECT 15.695 21.520 19.345 21.740 ;
        RECT 29.135 21.520 31.825 21.740 ;
        RECT 54.095 21.100 60.145 21.740 ;
        RECT 150.095 21.520 152.305 21.740 ;
        RECT 155.855 21.520 156.100 21.740 ;
        RECT 170.735 21.520 172.465 21.740 ;
        RECT 181.775 21.520 183.985 21.740 ;
        RECT 299.855 21.520 301.585 21.740 ;
        RECT 309.455 21.520 309.700 21.740 ;
        RECT 312.335 21.320 312.625 21.740 ;
        RECT 139.055 21.740 142.705 21.940 ;
        RECT 148.655 21.740 152.305 21.940 ;
        RECT 155.855 21.740 156.145 21.940 ;
        RECT 161.135 21.740 164.785 21.940 ;
        RECT 170.735 21.740 174.385 21.940 ;
        RECT 180.335 21.740 183.985 21.940 ;
        RECT 189.935 21.740 204.145 21.940 ;
        RECT 260.975 21.520 263.665 21.940 ;
        RECT 296.975 21.740 301.585 21.940 ;
        RECT 309.455 21.740 315.505 21.940 ;
        RECT 29.135 21.740 67.345 21.940 ;
        RECT 9.455 21.740 19.345 22.160 ;
        RECT 23.855 21.520 27.505 22.160 ;
        RECT 29.135 21.940 38.020 22.160 ;
        RECT 54.095 21.940 67.345 22.160 ;
        RECT 71.855 21.740 75.505 22.160 ;
        RECT 100.655 21.520 104.305 22.160 ;
        RECT 129.455 21.740 133.105 22.160 ;
        RECT 140.975 21.940 142.705 22.160 ;
        RECT 148.655 21.940 150.865 22.160 ;
        RECT 162.575 21.940 164.785 22.160 ;
        RECT 195.740 21.940 204.145 22.160 ;
        RECT 218.735 21.740 222.385 22.160 ;
        RECT 228.335 21.520 231.985 22.160 ;
        RECT 237.935 21.740 241.585 22.160 ;
        RECT 262.895 21.940 263.665 22.160 ;
        RECT 275.375 21.740 276.625 22.160 ;
        RECT 305.135 21.520 308.785 22.160 ;
        RECT 309.455 21.940 315.460 22.160 ;
        RECT 8.975 22.160 38.020 22.360 ;
        RECT 54.095 22.160 83.185 22.360 ;
        RECT 140.975 22.160 150.865 22.360 ;
        RECT 193.775 21.940 194.065 22.360 ;
        RECT 262.895 22.160 278.500 22.360 ;
        RECT 95.375 22.160 134.065 22.360 ;
        RECT 195.740 22.160 225.745 22.360 ;
        RECT 227.375 22.160 232.900 22.360 ;
        RECT 234.620 22.160 252.100 22.360 ;
        RECT 37.775 22.360 38.020 22.580 ;
        RECT 76.175 22.360 83.185 22.580 ;
        RECT 95.375 22.360 95.620 22.580 ;
        RECT 133.820 22.360 134.065 22.580 ;
        RECT 140.975 22.360 147.285 22.580 ;
        RECT 162.575 22.160 168.625 22.580 ;
        RECT 203.855 22.360 225.745 22.580 ;
        RECT 227.375 22.360 230.980 22.580 ;
        RECT 232.175 22.360 232.900 22.580 ;
        RECT 234.620 22.360 237.205 22.580 ;
        RECT 251.855 22.360 252.100 22.580 ;
        RECT 278.255 22.360 278.500 22.580 ;
        RECT 301.775 22.160 315.460 22.580 ;
        RECT 10.475 22.360 12.405 22.780 ;
        RECT 14.255 22.360 17.905 22.780 ;
        RECT 19.055 22.360 29.425 22.780 ;
        RECT 62.255 22.360 65.905 22.780 ;
        RECT 100.395 22.360 108.145 22.780 ;
        RECT 203.855 22.580 230.980 22.780 ;
        RECT 232.175 22.580 237.205 22.780 ;
        RECT 37.775 22.580 47.620 22.780 ;
        RECT 133.820 22.580 147.285 22.780 ;
        RECT 153.455 22.580 185.380 22.780 ;
        RECT 237.935 22.360 242.980 22.780 ;
        RECT 251.855 22.580 261.700 22.780 ;
        RECT 268.175 22.360 277.060 22.780 ;
        RECT 300.335 22.580 315.460 22.780 ;
        RECT 27.695 22.780 29.425 23.000 ;
        RECT 35.855 22.360 36.145 23.000 ;
        RECT 37.775 22.780 42.820 23.000 ;
        RECT 47.375 22.780 47.620 23.000 ;
        RECT 55.435 22.360 57.365 23.000 ;
        RECT 76.175 22.580 95.620 23.000 ;
        RECT 133.820 22.780 137.380 23.000 ;
        RECT 144.860 22.780 147.285 23.000 ;
        RECT 153.455 22.780 159.985 23.000 ;
        RECT 185.135 22.780 185.380 23.000 ;
        RECT 190.315 22.580 192.245 23.000 ;
        RECT 195.740 22.360 195.940 23.000 ;
        RECT 203.855 22.780 206.065 23.000 ;
        RECT 232.220 22.780 237.205 23.000 ;
        RECT 237.935 22.780 238.660 23.000 ;
        RECT 242.735 22.780 242.980 23.000 ;
        RECT 246.575 22.360 249.745 23.000 ;
        RECT 251.855 22.780 252.580 23.000 ;
        RECT 261.455 22.780 261.700 23.000 ;
        RECT 268.175 22.780 271.345 23.000 ;
        RECT 276.860 22.780 277.060 23.000 ;
        RECT 278.255 22.580 278.545 23.000 ;
        RECT 280.235 22.580 282.165 23.000 ;
        RECT 291.215 22.580 294.385 23.000 ;
        RECT 300.335 22.780 307.825 23.000 ;
        RECT 315.215 22.780 315.460 23.000 ;
        RECT 23.855 22.780 25.585 23.200 ;
        RECT 27.695 23.000 30.385 23.200 ;
        RECT 32.495 23.000 42.820 23.200 ;
        RECT 47.375 23.000 58.180 23.200 ;
        RECT 67.055 23.000 96.145 23.200 ;
        RECT 144.860 23.000 159.985 23.200 ;
        RECT 211.055 22.780 230.065 23.200 ;
        RECT 275.855 22.780 276.145 23.200 ;
        RECT 276.860 23.000 307.825 23.200 ;
        RECT 315.215 23.000 318.385 23.200 ;
        RECT 19.580 22.780 23.140 23.200 ;
        RECT 124.655 23.000 137.380 23.200 ;
        RECT 232.220 23.000 238.660 23.200 ;
        RECT 242.735 23.000 252.580 23.200 ;
        RECT 261.455 23.000 271.345 23.200 ;
        RECT 57.935 23.200 58.180 23.420 ;
        RECT 92.495 23.200 96.145 23.420 ;
        RECT 114.095 23.000 116.785 23.420 ;
        RECT 124.655 23.200 127.345 23.420 ;
        RECT 139.055 22.780 140.785 23.420 ;
        RECT 144.860 23.200 146.545 23.420 ;
        RECT 174.575 22.780 177.265 23.420 ;
        RECT 185.135 23.000 195.940 23.420 ;
        RECT 203.375 23.000 206.065 23.420 ;
        RECT 242.735 23.200 245.425 23.420 ;
        RECT 252.335 23.200 252.580 23.420 ;
        RECT 261.455 23.200 263.185 23.420 ;
        RECT 269.135 23.200 271.345 23.420 ;
        RECT 275.900 23.200 276.145 23.420 ;
        RECT 276.860 23.200 283.825 23.420 ;
        RECT 34.895 23.200 40.945 23.620 ;
        RECT 57.935 23.420 62.980 23.620 ;
        RECT 71.375 23.200 79.345 23.620 ;
        RECT 82.895 23.200 91.780 23.620 ;
        RECT 138.575 23.420 146.545 23.620 ;
        RECT 200.975 23.420 207.025 23.620 ;
        RECT 220.175 23.200 226.225 23.620 ;
        RECT 232.220 23.200 235.825 23.620 ;
        RECT 239.375 23.420 245.425 23.620 ;
        RECT 269.135 23.420 274.225 23.620 ;
        RECT 275.900 23.420 283.825 23.620 ;
        RECT 102.095 23.420 110.980 23.620 ;
        RECT 111.695 23.420 120.580 23.620 ;
        RECT 130.895 23.200 137.380 23.620 ;
        RECT 162.620 23.420 198.820 23.620 ;
        RECT 252.335 23.420 255.460 23.620 ;
        RECT 264.860 23.200 268.465 23.620 ;
        RECT 287.375 23.200 297.220 23.620 ;
        RECT 6.575 23.420 12.145 23.840 ;
        RECT 19.580 23.200 19.780 23.840 ;
        RECT 22.940 23.200 23.140 23.840 ;
        RECT 34.895 23.620 39.505 23.840 ;
        RECT 42.620 23.200 42.820 23.840 ;
        RECT 62.255 23.620 62.980 23.840 ;
        RECT 73.775 23.620 79.345 23.840 ;
        RECT 91.580 23.620 91.780 23.840 ;
        RECT 92.495 23.420 98.545 23.840 ;
        RECT 102.095 23.620 102.865 23.840 ;
        RECT 110.255 23.620 110.980 23.840 ;
        RECT 111.695 23.620 118.180 23.840 ;
        RECT 119.855 23.620 120.580 23.840 ;
        RECT 121.295 23.420 127.345 23.840 ;
        RECT 130.895 23.620 135.940 23.840 ;
        RECT 137.180 23.620 137.380 23.840 ;
        RECT 138.575 23.620 141.220 23.840 ;
        RECT 162.620 23.620 162.865 23.840 ;
        RECT 201.455 23.620 207.025 23.840 ;
        RECT 232.220 23.620 234.385 23.840 ;
        RECT 238.460 23.200 238.660 23.840 ;
        RECT 252.335 23.620 253.585 23.840 ;
        RECT 259.055 23.420 263.185 23.840 ;
        RECT 264.860 23.620 265.060 23.840 ;
        RECT 267.695 23.620 268.465 23.840 ;
        RECT 269.135 23.620 272.785 23.840 ;
        RECT 277.775 23.620 283.825 23.840 ;
        RECT 287.375 23.620 287.620 23.840 ;
        RECT 296.975 23.620 297.220 23.840 ;
        RECT 6.140 23.840 32.305 24.040 ;
        RECT 33.455 23.840 33.745 24.040 ;
        RECT 52.655 23.840 56.260 24.040 ;
        RECT 62.255 23.840 70.180 24.040 ;
        RECT 81.455 23.840 81.745 24.040 ;
        RECT 91.580 23.840 102.865 24.040 ;
        RECT 110.255 23.840 118.180 24.040 ;
        RECT 119.855 23.840 135.940 24.040 ;
        RECT 142.415 23.620 146.065 24.040 ;
        RECT 164.975 23.620 167.665 24.040 ;
        RECT 171.695 23.620 176.785 24.040 ;
        RECT 190.895 23.620 195.985 24.040 ;
        RECT 199.535 23.840 199.825 24.040 ;
        RECT 201.455 23.840 207.985 24.040 ;
        RECT 209.135 23.840 209.425 24.040 ;
        RECT 239.855 23.620 244.945 24.040 ;
        RECT 247.535 23.840 247.825 24.040 ;
        RECT 257.135 23.840 257.425 24.040 ;
        RECT 258.095 23.840 265.060 24.040 ;
        RECT 266.735 23.620 267.025 24.040 ;
        RECT 289.775 23.620 292.465 24.040 ;
        RECT 295.535 23.620 295.825 24.040 ;
        RECT 308.975 23.840 311.665 24.040 ;
        RECT 73.775 23.840 79.780 24.040 ;
        RECT 137.180 23.840 141.220 24.040 ;
        RECT 150.575 23.840 162.865 24.040 ;
        RECT 277.775 23.840 287.620 24.040 ;
        RECT 296.975 23.840 303.940 24.040 ;
        RECT 6.140 24.040 6.385 24.260 ;
        RECT 33.500 24.040 33.745 24.260 ;
        RECT 34.415 23.840 39.505 24.260 ;
        RECT 42.620 23.840 43.345 24.260 ;
        RECT 46.895 23.840 49.585 24.260 ;
        RECT 56.015 24.040 56.260 24.260 ;
        RECT 73.775 24.040 77.905 24.260 ;
        RECT 81.500 24.040 81.745 24.260 ;
        RECT 85.295 23.620 87.985 24.260 ;
        RECT 130.415 24.040 135.940 24.260 ;
        RECT 137.180 24.040 138.865 24.260 ;
        RECT 143.900 24.040 146.065 24.260 ;
        RECT 150.575 24.040 154.705 24.260 ;
        RECT 162.095 24.040 162.865 24.260 ;
        RECT 164.975 24.040 167.185 24.260 ;
        RECT 193.295 24.040 195.985 24.260 ;
        RECT 198.620 23.620 198.820 24.260 ;
        RECT 199.580 24.040 199.825 24.260 ;
        RECT 201.455 24.040 207.025 24.260 ;
        RECT 209.180 24.040 209.425 24.260 ;
        RECT 210.095 23.840 215.185 24.260 ;
        RECT 219.260 23.200 219.460 24.260 ;
        RECT 220.655 23.620 224.305 24.260 ;
        RECT 228.335 23.840 234.385 24.260 ;
        RECT 237.935 23.840 238.660 24.260 ;
        RECT 239.855 24.040 243.985 24.260 ;
        RECT 247.580 24.040 247.825 24.260 ;
        RECT 248.495 23.840 253.585 24.260 ;
        RECT 255.260 23.620 255.460 24.260 ;
        RECT 257.180 24.040 257.425 24.260 ;
        RECT 258.095 24.040 264.625 24.260 ;
        RECT 266.780 24.040 267.025 24.260 ;
        RECT 267.695 23.840 272.785 24.260 ;
        RECT 277.775 24.040 283.825 24.260 ;
        RECT 286.895 24.040 287.620 24.260 ;
        RECT 289.775 24.040 291.985 24.260 ;
        RECT 295.580 24.040 295.825 24.260 ;
        RECT 296.975 24.040 303.025 24.260 ;
        RECT 308.975 24.040 311.185 24.260 ;
        RECT 6.095 24.260 6.385 24.460 ;
        RECT 8.015 24.040 12.100 24.460 ;
        RECT 17.615 24.040 21.745 24.460 ;
        RECT 33.500 24.260 40.945 24.460 ;
        RECT 56.015 24.260 60.145 24.460 ;
        RECT 81.500 24.260 88.945 24.460 ;
        RECT 104.015 24.260 109.105 24.460 ;
        RECT 119.900 24.040 127.345 24.460 ;
        RECT 130.415 24.260 138.865 24.460 ;
        RECT 209.180 24.260 216.625 24.460 ;
        RECT 247.580 24.260 255.460 24.460 ;
        RECT 257.180 24.260 264.625 24.460 ;
        RECT 266.780 24.260 274.225 24.460 ;
        RECT 275.375 24.260 283.825 24.460 ;
        RECT 286.895 24.260 291.985 24.460 ;
        RECT 25.820 24.040 31.780 24.460 ;
        RECT 62.300 24.040 70.180 24.460 ;
        RECT 91.580 24.040 97.105 24.460 ;
        RECT 98.780 24.040 102.820 24.460 ;
        RECT 143.900 24.260 154.705 24.460 ;
        RECT 162.095 24.260 167.185 24.460 ;
        RECT 193.295 24.260 198.820 24.460 ;
        RECT 219.260 24.260 224.785 24.460 ;
        RECT 225.455 24.260 243.985 24.460 ;
        RECT 306.095 24.260 311.185 24.460 ;
        RECT 11.855 24.460 12.100 24.680 ;
        RECT 15.695 24.040 15.985 24.680 ;
        RECT 25.820 24.460 26.065 24.680 ;
        RECT 27.215 24.460 31.780 24.680 ;
        RECT 33.500 24.460 35.665 24.680 ;
        RECT 42.620 24.260 50.545 24.680 ;
        RECT 56.015 24.460 59.620 24.680 ;
        RECT 62.300 24.460 64.945 24.680 ;
        RECT 66.095 24.460 70.180 24.680 ;
        RECT 72.815 24.260 77.905 24.680 ;
        RECT 93.935 24.460 97.105 24.680 ;
        RECT 102.095 24.460 102.820 24.680 ;
        RECT 104.015 24.460 107.185 24.680 ;
        RECT 110.300 24.040 110.500 24.680 ;
        RECT 111.215 24.040 116.305 24.680 ;
        RECT 132.815 24.460 138.865 24.680 ;
        RECT 141.020 24.040 141.220 24.680 ;
        RECT 143.900 24.460 144.145 24.680 ;
        RECT 152.015 24.460 154.705 24.680 ;
        RECT 162.095 24.460 163.345 24.680 ;
        RECT 164.495 24.460 167.185 24.680 ;
        RECT 174.575 24.040 174.865 24.680 ;
        RECT 193.295 24.460 196.465 24.680 ;
        RECT 198.620 24.460 198.820 24.680 ;
        RECT 199.580 24.260 207.025 24.680 ;
        RECT 209.180 24.460 210.865 24.680 ;
        RECT 222.095 24.460 224.785 24.680 ;
        RECT 225.455 24.460 226.225 24.680 ;
        RECT 241.295 24.460 243.985 24.680 ;
        RECT 255.260 24.460 255.460 24.680 ;
        RECT 257.180 24.460 264.100 24.680 ;
        RECT 276.335 24.460 283.825 24.680 ;
        RECT 288.815 24.460 291.985 24.680 ;
        RECT 295.580 24.260 303.025 24.680 ;
        RECT 303.740 24.040 303.940 24.680 ;
        RECT 306.095 24.460 306.865 24.680 ;
        RECT 308.015 24.460 311.185 24.680 ;
        RECT 8.060 24.460 10.705 24.880 ;
        RECT 11.855 24.680 12.145 24.880 ;
        RECT 21.935 24.680 26.065 24.880 ;
        RECT 27.215 24.680 35.665 24.880 ;
        RECT 102.095 24.680 107.185 24.880 ;
        RECT 132.815 24.680 144.145 24.880 ;
        RECT 149.180 24.460 150.820 24.880 ;
        RECT 152.015 24.680 163.345 24.880 ;
        RECT 238.460 24.460 239.620 24.880 ;
        RECT 270.575 24.460 273.265 24.880 ;
        RECT 295.535 24.680 306.865 24.880 ;
        RECT 308.015 24.680 312.145 24.880 ;
        RECT 14.780 24.680 16.465 24.880 ;
        RECT 42.620 24.680 59.620 24.880 ;
        RECT 164.495 24.680 178.660 24.880 ;
        RECT 255.260 24.680 264.100 24.880 ;
        RECT 8.060 24.880 8.260 25.100 ;
        RECT 14.780 24.880 15.025 25.100 ;
        RECT 16.220 24.880 16.465 25.100 ;
        RECT 18.095 24.460 20.785 25.100 ;
        RECT 21.935 24.880 24.580 25.100 ;
        RECT 32.015 24.880 35.665 25.100 ;
        RECT 37.295 24.460 39.985 25.100 ;
        RECT 42.620 24.880 54.385 25.100 ;
        RECT 59.420 24.880 59.620 25.100 ;
        RECT 62.255 24.680 64.945 25.100 ;
        RECT 66.095 24.680 78.865 25.100 ;
        RECT 79.580 24.040 79.780 25.100 ;
        RECT 91.580 24.460 92.785 25.100 ;
        RECT 93.935 24.680 98.065 25.100 ;
        RECT 98.780 24.460 98.980 25.100 ;
        RECT 104.060 24.880 107.185 25.100 ;
        RECT 110.300 24.680 117.745 25.100 ;
        RECT 123.695 24.460 126.385 25.100 ;
        RECT 132.815 24.880 137.380 25.100 ;
        RECT 159.695 24.880 163.345 25.100 ;
        RECT 164.495 24.880 169.060 25.100 ;
        RECT 192.335 24.680 196.465 25.100 ;
        RECT 198.620 24.680 210.865 25.100 ;
        RECT 212.975 24.460 215.665 25.100 ;
        RECT 219.260 24.460 220.465 25.100 ;
        RECT 222.095 24.680 226.225 25.100 ;
        RECT 226.895 24.460 228.625 25.100 ;
        RECT 232.175 24.460 234.865 25.100 ;
        RECT 239.375 24.880 239.620 25.100 ;
        RECT 241.295 24.680 245.425 25.100 ;
        RECT 251.375 24.460 254.065 25.100 ;
        RECT 255.260 24.880 259.345 25.100 ;
        RECT 263.900 24.880 264.100 25.100 ;
        RECT 270.575 24.880 271.825 25.100 ;
        RECT 276.335 24.680 284.305 25.100 ;
        RECT 288.815 24.680 292.945 25.100 ;
        RECT 308.495 24.880 312.145 25.100 ;
        RECT 14.735 25.100 15.025 25.300 ;
        RECT 16.220 25.100 24.580 25.300 ;
        RECT 32.015 25.100 54.385 25.300 ;
        RECT 59.420 25.100 98.980 25.300 ;
        RECT 101.615 25.100 101.905 25.300 ;
        RECT 104.060 25.100 137.380 25.300 ;
        RECT 138.575 24.880 142.660 25.300 ;
        RECT 153.980 24.880 156.580 25.300 ;
        RECT 159.695 25.100 169.060 25.300 ;
        RECT 263.900 25.100 271.825 25.300 ;
        RECT 275.900 25.100 293.425 25.300 ;
        RECT 298.895 24.880 303.025 25.300 ;
        RECT 308.495 25.100 312.625 25.300 ;
        RECT 174.095 24.880 178.660 25.300 ;
        RECT 191.855 25.100 235.825 25.300 ;
        RECT 5.615 25.100 8.260 25.520 ;
        RECT 16.220 25.300 20.305 25.520 ;
        RECT 53.615 25.300 54.385 25.520 ;
        RECT 101.660 25.300 101.905 25.520 ;
        RECT 104.060 25.300 106.705 25.520 ;
        RECT 142.460 25.300 142.660 25.520 ;
        RECT 150.620 24.880 150.820 25.520 ;
        RECT 153.980 25.300 154.180 25.520 ;
        RECT 163.055 25.300 169.060 25.520 ;
        RECT 174.095 25.300 177.745 25.520 ;
        RECT 178.460 25.300 178.660 25.520 ;
        RECT 191.855 25.300 194.545 25.520 ;
        RECT 231.260 25.300 235.825 25.520 ;
        RECT 239.375 25.100 259.345 25.520 ;
        RECT 261.935 24.880 262.225 25.520 ;
        RECT 271.055 25.300 271.825 25.520 ;
        RECT 275.900 25.300 276.100 25.520 ;
        RECT 4.175 25.520 12.625 25.720 ;
        RECT 15.215 25.520 20.305 25.720 ;
        RECT 44.015 25.300 49.105 25.720 ;
        RECT 53.615 25.520 58.225 25.720 ;
        RECT 61.775 25.300 62.065 25.720 ;
        RECT 63.215 25.300 68.305 25.720 ;
        RECT 74.780 25.300 76.465 25.720 ;
        RECT 82.415 25.300 87.505 25.720 ;
        RECT 93.980 25.300 98.980 25.720 ;
        RECT 101.660 25.520 106.705 25.720 ;
        RECT 120.815 25.300 125.905 25.720 ;
        RECT 133.295 25.300 135.985 25.720 ;
        RECT 163.055 25.520 172.945 25.720 ;
        RECT 178.460 25.520 194.545 25.720 ;
        RECT 200.495 25.300 205.585 25.720 ;
        RECT 211.055 25.300 211.500 25.720 ;
        RECT 231.260 25.520 263.185 25.720 ;
        RECT 271.055 25.520 276.100 25.720 ;
        RECT 299.375 25.300 302.065 25.720 ;
        RECT 6.575 25.720 12.625 25.940 ;
        RECT 61.820 25.720 62.065 25.940 ;
        RECT 63.215 25.720 67.345 25.940 ;
        RECT 139.580 25.300 139.780 25.940 ;
        RECT 142.460 25.520 145.105 25.940 ;
        RECT 150.620 25.520 154.180 25.940 ;
        RECT 172.700 25.720 172.945 25.940 ;
        RECT 173.615 25.520 177.745 25.940 ;
        RECT 178.460 25.720 192.145 25.940 ;
        RECT 271.535 25.720 276.100 25.940 ;
        RECT 277.295 25.300 282.385 25.940 ;
        RECT 288.860 25.300 290.545 25.940 ;
        RECT 299.375 25.720 301.585 25.940 ;
        RECT 6.575 25.940 15.025 26.140 ;
        RECT 139.580 25.940 154.180 26.140 ;
        RECT 172.700 25.940 192.145 26.140 ;
        RECT 271.535 25.940 291.025 26.140 ;
        RECT 296.495 25.940 301.585 26.140 ;
        RECT 61.820 25.940 67.345 26.140 ;
        RECT 61.820 26.140 62.985 26.360 ;
        RECT 66.095 26.140 67.345 26.360 ;
        RECT 188.495 26.140 192.145 26.360 ;
        RECT 290.780 26.140 291.025 26.360 ;
        RECT 296.495 26.140 300.625 26.360 ;
        RECT 61.055 26.360 62.985 26.560 ;
        RECT 66.095 26.360 68.785 26.560 ;
        RECT 142.895 26.140 145.585 26.560 ;
        RECT 150.975 26.140 152.905 26.560 ;
        RECT 280.175 26.140 282.865 26.560 ;
        RECT 285.855 26.140 287.785 26.560 ;
        RECT 290.780 26.360 300.625 26.560 ;
        RECT 142.895 26.560 144.145 26.780 ;
        RECT 188.495 26.360 193.105 26.780 ;
        RECT 290.780 26.560 300.145 26.780 ;
        RECT 137.615 26.780 144.145 26.980 ;
        RECT 187.055 26.780 195.025 26.980 ;
        RECT 290.255 26.780 300.145 26.980 ;
        RECT 295.055 26.980 300.145 27.200 ;
        RECT 295.055 27.200 301.585 27.400 ;
        RECT 1.775 27.200 2.980 27.400 ;
        RECT 2.780 27.400 2.980 27.620 ;
        RECT 2.780 27.620 4.465 28.040 ;
        RECT 249.935 27.620 254.545 28.040 ;
        RECT 2.000 28.040 306.385 28.240 ;
        RECT 62.255 31.400 69.745 31.600 ;
        RECT 234.575 31.400 243.985 31.600 ;
        RECT 285.935 31.400 293.425 31.600 ;
        RECT 19.535 31.400 22.705 31.820 ;
        RECT 62.255 31.600 63.460 31.820 ;
        RECT 131.855 31.400 136.465 31.820 ;
        RECT 144.815 31.400 147.985 31.820 ;
        RECT 234.575 31.600 239.140 31.820 ;
        RECT 285.935 31.600 287.140 31.820 ;
        RECT 15.215 31.820 63.460 32.020 ;
        RECT 100.700 31.820 239.140 32.020 ;
        RECT 277.295 31.820 287.140 32.020 ;
        RECT 63.215 32.020 63.460 32.240 ;
        RECT 90.095 31.820 98.545 32.240 ;
        RECT 100.700 32.020 100.900 32.240 ;
        RECT 238.895 32.020 239.140 32.240 ;
        RECT 277.295 32.020 277.540 32.240 ;
        RECT 286.895 32.020 287.140 32.240 ;
        RECT 18.575 32.020 22.225 32.440 ;
        RECT 23.375 32.020 31.345 32.440 ;
        RECT 32.975 32.020 40.945 32.440 ;
        RECT 42.575 32.020 50.545 32.440 ;
        RECT 52.175 32.020 60.145 32.440 ;
        RECT 63.215 32.240 100.900 32.440 ;
        RECT 103.055 32.020 108.145 32.440 ;
        RECT 111.695 32.020 117.745 32.440 ;
        RECT 121.295 32.020 127.345 32.440 ;
        RECT 128.975 32.020 136.945 32.440 ;
        RECT 138.575 32.020 146.545 32.440 ;
        RECT 148.175 32.020 156.145 32.440 ;
        RECT 160.655 32.020 168.625 32.440 ;
        RECT 170.255 32.020 178.225 32.440 ;
        RECT 179.855 32.020 187.825 32.440 ;
        RECT 188.975 32.020 197.425 32.440 ;
        RECT 199.055 32.020 207.025 32.440 ;
        RECT 208.655 32.020 216.625 32.440 ;
        RECT 218.255 32.020 226.225 32.440 ;
        RECT 227.855 32.020 235.825 32.440 ;
        RECT 283.535 32.020 283.825 32.440 ;
        RECT 286.895 32.240 306.385 32.440 ;
        RECT 238.895 32.240 277.540 32.440 ;
        RECT 170.255 32.440 176.305 32.660 ;
        RECT 238.895 32.440 245.425 32.660 ;
        RECT 275.855 32.440 277.540 32.660 ;
        RECT 283.535 32.440 283.780 32.660 ;
        RECT 304.655 32.440 306.385 32.660 ;
        RECT 71.375 32.440 79.345 32.860 ;
        RECT 80.975 32.440 88.945 32.860 ;
        RECT 169.775 32.660 176.305 32.860 ;
        RECT 237.455 32.660 245.425 32.860 ;
        RECT 247.055 32.440 255.025 32.860 ;
        RECT 256.655 32.440 264.625 32.860 ;
        RECT 266.255 32.440 274.225 32.860 ;
        RECT 275.855 32.660 283.780 32.860 ;
        RECT 295.055 32.440 303.025 32.860 ;
        RECT 304.655 32.660 312.625 32.860 ;
        RECT 3.215 35.180 59.140 35.380 ;
        RECT 305.615 35.180 312.625 35.380 ;
        RECT 58.895 35.380 59.140 35.600 ;
        RECT 305.615 35.380 306.385 35.600 ;
        RECT 58.895 35.600 306.385 35.800 ;
        RECT 306.575 38.960 316.945 39.160 ;
        RECT 19.055 38.960 38.545 39.380 ;
        RECT 306.575 39.160 311.620 39.380 ;
        RECT 3.215 39.380 311.620 39.580 ;
        RECT 311.375 39.580 311.620 39.800 ;
        RECT 9.500 39.580 19.345 40.000 ;
        RECT 26.735 39.580 31.345 40.000 ;
        RECT 36.335 39.580 40.945 40.000 ;
        RECT 45.935 39.580 50.545 40.000 ;
        RECT 55.535 39.580 60.145 40.000 ;
        RECT 65.135 39.580 69.745 40.000 ;
        RECT 84.335 39.580 88.945 40.000 ;
        RECT 103.535 39.580 108.145 40.000 ;
        RECT 122.735 39.580 127.345 40.000 ;
        RECT 132.335 39.580 136.945 40.000 ;
        RECT 141.935 39.580 146.545 40.000 ;
        RECT 231.215 39.580 235.825 40.000 ;
        RECT 250.415 39.580 255.025 40.000 ;
        RECT 279.215 39.580 283.825 40.000 ;
        RECT 298.415 39.580 303.025 40.000 ;
        RECT 305.135 39.580 308.305 40.000 ;
        RECT 311.375 39.800 311.665 40.000 ;
        RECT 160.175 39.580 160.465 40.220 ;
        RECT 173.615 39.580 178.225 40.220 ;
        RECT 183.215 39.580 187.825 40.220 ;
        RECT 192.815 39.580 197.425 40.220 ;
        RECT 212.015 39.580 216.625 40.220 ;
        RECT 221.615 39.580 226.225 40.220 ;
        RECT 260.015 39.580 264.625 40.220 ;
        RECT 269.615 39.580 274.225 40.220 ;
        RECT 279.215 40.000 280.945 40.220 ;
        RECT 150.095 40.220 230.065 40.420 ;
        RECT 236.975 40.220 244.465 40.420 ;
        RECT 256.175 40.220 280.945 40.420 ;
        RECT 9.500 40.000 9.700 40.640 ;
        RECT 228.335 40.420 230.065 40.640 ;
        RECT 243.695 40.420 244.465 40.640 ;
        RECT 91.055 40.640 95.185 40.840 ;
        RECT 100.655 40.640 104.305 40.840 ;
        RECT 119.855 40.640 123.505 40.840 ;
        RECT 170.735 40.420 174.385 40.840 ;
        RECT 238.895 40.420 243.025 40.840 ;
        RECT 266.735 40.420 270.385 40.840 ;
        RECT 276.335 40.420 279.985 40.840 ;
        RECT 9.500 40.640 13.585 40.840 ;
        RECT 9.500 40.840 10.180 41.060 ;
        RECT 11.375 40.840 13.585 41.060 ;
        RECT 14.255 40.640 19.825 41.060 ;
        RECT 23.855 40.640 30.865 41.060 ;
        RECT 33.455 40.640 37.105 41.060 ;
        RECT 52.655 40.640 56.305 41.060 ;
        RECT 62.255 40.640 65.905 41.060 ;
        RECT 67.535 40.640 69.745 41.060 ;
        RECT 71.855 40.640 75.505 41.060 ;
        RECT 77.615 40.640 79.345 41.060 ;
        RECT 81.455 40.640 85.105 41.060 ;
        RECT 92.975 40.840 95.185 41.060 ;
        RECT 100.655 40.840 102.865 41.060 ;
        RECT 120.815 40.840 123.505 41.060 ;
        RECT 124.655 40.640 134.545 41.060 ;
        RECT 139.055 40.640 142.705 41.060 ;
        RECT 189.935 40.420 193.585 41.060 ;
        RECT 209.135 40.420 212.785 41.060 ;
        RECT 228.335 40.640 231.985 41.060 ;
        RECT 239.375 40.840 243.025 41.060 ;
        RECT 243.695 40.640 245.425 41.060 ;
        RECT 247.535 40.640 251.185 41.060 ;
        RECT 268.655 40.840 270.385 41.060 ;
        RECT 276.335 40.840 278.500 41.060 ;
        RECT 11.375 41.060 22.180 41.260 ;
        RECT 120.815 41.060 150.385 41.260 ;
        RECT 182.735 41.060 233.425 41.260 ;
        RECT 239.375 41.060 265.540 41.260 ;
        RECT 268.655 41.060 278.500 41.260 ;
        RECT 22.895 41.060 88.420 41.260 ;
        RECT 92.975 41.060 102.865 41.260 ;
        RECT 9.455 41.060 10.180 41.480 ;
        RECT 21.455 41.260 22.180 41.480 ;
        RECT 22.895 41.260 31.780 41.480 ;
        RECT 88.220 41.260 88.420 41.480 ;
        RECT 92.975 41.260 98.065 41.480 ;
        RECT 100.655 41.260 102.865 41.480 ;
        RECT 120.815 41.260 121.585 41.480 ;
        RECT 182.735 41.260 192.145 41.480 ;
        RECT 1.680 41.480 10.180 41.680 ;
        RECT 16.095 41.260 18.025 41.680 ;
        RECT 21.455 41.480 31.780 41.680 ;
        RECT 34.895 41.260 44.785 41.680 ;
        RECT 61.055 41.260 62.985 41.680 ;
        RECT 88.220 41.480 98.065 41.680 ;
        RECT 100.655 41.480 103.345 41.680 ;
        RECT 153.455 41.480 160.465 41.680 ;
        RECT 163.055 41.480 192.145 41.680 ;
        RECT 199.100 41.260 204.145 41.680 ;
        RECT 240.895 41.260 256.465 41.680 ;
        RECT 280.175 41.480 282.865 41.680 ;
        RECT 76.655 41.260 86.545 41.680 ;
        RECT 124.175 41.260 146.065 41.680 ;
        RECT 43.055 41.680 44.785 41.900 ;
        RECT 61.055 41.680 62.020 41.900 ;
        RECT 76.655 41.680 83.665 41.900 ;
        RECT 85.295 41.680 86.545 41.900 ;
        RECT 92.495 41.680 98.065 41.900 ;
        RECT 100.655 41.680 102.385 41.900 ;
        RECT 106.015 41.480 107.945 41.900 ;
        RECT 110.255 41.480 111.985 41.900 ;
        RECT 115.055 41.480 117.265 41.900 ;
        RECT 119.855 41.480 121.585 41.900 ;
        RECT 124.175 41.680 124.420 41.900 ;
        RECT 134.255 41.680 146.065 41.900 ;
        RECT 150.975 41.480 152.905 41.900 ;
        RECT 153.455 41.680 159.505 41.900 ;
        RECT 163.055 41.680 164.785 41.900 ;
        RECT 195.935 41.260 197.865 41.900 ;
        RECT 199.100 41.680 203.185 41.900 ;
        RECT 265.340 41.260 265.540 41.900 ;
        RECT 277.775 41.260 278.500 41.900 ;
        RECT 280.175 41.680 282.820 41.900 ;
        RECT 300.815 41.480 303.505 41.900 ;
        RECT 4.655 41.680 8.305 42.100 ;
        RECT 38.255 41.680 42.385 42.100 ;
        RECT 43.055 41.900 46.705 42.100 ;
        RECT 85.295 41.900 87.985 42.100 ;
        RECT 129.455 41.680 133.105 42.100 ;
        RECT 134.255 41.900 159.505 42.100 ;
        RECT 161.135 41.900 164.785 42.100 ;
        RECT 180.335 41.680 183.985 42.100 ;
        RECT 193.775 41.900 203.185 42.100 ;
        RECT 218.735 41.900 222.385 42.100 ;
        RECT 230.255 41.900 240.100 42.100 ;
        RECT 257.135 41.900 260.785 42.100 ;
        RECT 265.295 41.900 282.820 42.100 ;
        RECT 54.095 41.900 62.020 42.100 ;
        RECT 64.175 41.900 83.665 42.100 ;
        RECT 92.495 41.900 102.385 42.100 ;
        RECT 104.975 41.900 124.420 42.100 ;
        RECT 244.220 41.680 249.700 42.100 ;
        RECT 288.335 41.900 306.865 42.100 ;
        RECT 5.615 42.100 8.305 42.320 ;
        RECT 21.500 41.680 21.700 42.320 ;
        RECT 44.015 42.100 46.705 42.320 ;
        RECT 54.095 42.100 58.705 42.320 ;
        RECT 61.775 42.100 62.020 42.320 ;
        RECT 64.175 42.100 68.305 42.320 ;
        RECT 82.415 42.100 83.665 42.320 ;
        RECT 85.295 42.100 87.505 42.320 ;
        RECT 92.495 42.100 97.105 42.320 ;
        RECT 101.615 42.100 102.385 42.320 ;
        RECT 104.975 42.100 106.705 42.320 ;
        RECT 116.975 42.100 124.420 42.320 ;
        RECT 130.415 42.100 133.105 42.320 ;
        RECT 134.255 42.100 135.505 42.320 ;
        RECT 162.095 42.100 164.785 42.320 ;
        RECT 181.295 42.100 183.985 42.320 ;
        RECT 200.495 42.100 203.185 42.320 ;
        RECT 219.695 42.100 222.385 42.320 ;
        RECT 239.855 42.100 240.100 42.320 ;
        RECT 243.260 41.680 243.460 42.320 ;
        RECT 249.500 42.100 249.700 42.320 ;
        RECT 258.575 42.100 260.785 42.320 ;
        RECT 288.335 42.100 291.985 42.320 ;
        RECT 306.095 42.100 306.865 42.320 ;
        RECT 61.775 42.320 62.065 42.520 ;
        RECT 92.015 42.320 97.105 42.520 ;
        RECT 101.615 42.320 106.705 42.520 ;
        RECT 116.975 42.320 124.945 42.520 ;
        RECT 148.655 42.100 148.945 42.520 ;
        RECT 149.615 42.100 154.705 42.520 ;
        RECT 155.855 42.100 157.585 42.520 ;
        RECT 162.095 42.320 167.185 42.520 ;
        RECT 181.295 42.320 186.385 42.520 ;
        RECT 237.935 42.100 238.225 42.520 ;
        RECT 244.220 42.100 244.945 42.520 ;
        RECT 258.575 42.320 263.185 42.520 ;
        RECT 306.095 42.320 311.185 42.520 ;
        RECT 53.615 42.320 58.705 42.520 ;
        RECT 63.695 42.320 68.305 42.520 ;
        RECT 82.415 42.320 87.505 42.520 ;
        RECT 111.215 42.100 116.305 42.520 ;
        RECT 130.415 42.320 135.505 42.520 ;
        RECT 219.695 42.320 224.785 42.520 ;
        RECT 277.295 42.100 282.820 42.520 ;
        RECT 2.300 41.680 2.500 42.740 ;
        RECT 5.615 42.320 10.705 42.740 ;
        RECT 16.655 42.320 21.700 42.740 ;
        RECT 24.815 42.320 29.905 42.740 ;
        RECT 44.015 42.320 49.105 42.740 ;
        RECT 53.615 42.520 54.865 42.740 ;
        RECT 57.455 42.520 58.705 42.740 ;
        RECT 61.820 42.520 62.065 42.740 ;
        RECT 63.695 42.520 64.465 42.740 ;
        RECT 65.180 42.520 68.305 42.740 ;
        RECT 72.815 42.100 77.905 42.740 ;
        RECT 82.415 42.520 83.185 42.740 ;
        RECT 86.255 42.520 87.505 42.740 ;
        RECT 92.015 42.520 96.100 42.740 ;
        RECT 101.615 42.520 105.265 42.740 ;
        RECT 111.215 42.520 112.945 42.740 ;
        RECT 114.095 42.520 116.305 42.740 ;
        RECT 121.775 42.520 124.945 42.740 ;
        RECT 130.415 42.520 131.620 42.740 ;
        RECT 133.295 42.520 135.505 42.740 ;
        RECT 148.700 42.520 148.945 42.740 ;
        RECT 149.615 42.520 152.305 42.740 ;
        RECT 165.500 42.520 167.185 42.740 ;
        RECT 169.775 42.320 175.825 42.740 ;
        RECT 181.295 42.520 184.900 42.740 ;
        RECT 200.495 42.320 205.585 42.740 ;
        RECT 219.695 42.520 220.900 42.740 ;
        RECT 224.015 42.520 224.785 42.740 ;
        RECT 233.180 42.100 235.780 42.740 ;
        RECT 237.980 42.520 238.225 42.740 ;
        RECT 239.855 42.320 243.460 42.740 ;
        RECT 244.220 42.520 244.900 42.740 ;
        RECT 249.500 42.320 255.505 42.740 ;
        RECT 258.575 42.520 259.300 42.740 ;
        RECT 277.295 42.520 281.425 42.740 ;
        RECT 282.620 42.520 282.820 42.740 ;
        RECT 286.895 42.320 291.985 42.740 ;
        RECT 293.135 42.100 294.865 42.740 ;
        RECT 296.495 42.100 301.585 42.740 ;
        RECT 306.095 42.520 307.345 42.740 ;
        RECT 65.180 42.740 83.185 42.940 ;
        RECT 249.455 42.740 259.300 42.940 ;
        RECT 2.300 42.740 12.145 42.940 ;
        RECT 16.175 42.740 54.865 42.940 ;
        RECT 86.255 42.740 96.100 42.940 ;
        RECT 97.775 42.740 105.265 42.940 ;
        RECT 121.775 42.740 131.620 42.940 ;
        RECT 141.020 42.740 147.940 42.940 ;
        RECT 165.500 42.740 184.900 42.940 ;
        RECT 191.855 42.740 220.900 42.940 ;
        RECT 229.775 42.740 235.780 42.940 ;
        RECT 237.980 42.740 244.900 42.940 ;
        RECT 269.180 42.740 281.425 42.940 ;
        RECT 282.620 42.740 307.345 42.940 ;
        RECT 2.300 42.940 2.500 43.060 ;
        RECT 6.575 42.940 12.145 43.160 ;
        RECT 16.175 42.940 16.420 43.160 ;
        RECT 44.495 42.940 54.865 43.160 ;
        RECT 57.455 42.740 59.665 43.160 ;
        RECT 61.820 42.740 64.465 43.160 ;
        RECT 65.180 42.940 65.380 43.160 ;
        RECT 86.255 42.940 93.265 43.160 ;
        RECT 95.855 42.940 96.100 43.160 ;
        RECT 97.775 42.940 98.980 43.160 ;
        RECT 102.575 42.940 105.265 43.160 ;
        RECT 107.855 42.740 112.945 43.160 ;
        RECT 114.095 42.740 116.785 43.160 ;
        RECT 121.775 42.940 122.020 43.160 ;
        RECT 131.375 42.940 131.620 43.160 ;
        RECT 133.295 42.740 135.985 43.160 ;
        RECT 141.020 42.940 141.265 43.160 ;
        RECT 147.740 42.940 147.940 43.160 ;
        RECT 148.700 42.740 152.305 43.160 ;
        RECT 165.500 42.940 165.745 43.160 ;
        RECT 184.655 42.940 184.900 43.160 ;
        RECT 191.855 42.940 194.065 43.160 ;
        RECT 220.655 42.940 220.900 43.160 ;
        RECT 224.015 42.740 227.185 43.160 ;
        RECT 229.775 42.940 230.545 43.160 ;
        RECT 232.175 42.940 235.780 43.160 ;
        RECT 237.980 42.940 239.665 43.160 ;
        RECT 259.055 42.940 259.300 43.160 ;
        RECT 269.180 42.940 269.380 43.160 ;
        RECT 277.775 42.940 281.425 43.160 ;
        RECT 282.620 42.940 287.665 43.160 ;
        RECT 293.660 42.940 307.345 43.160 ;
        RECT 2.000 43.060 2.500 43.360 ;
        RECT 6.575 43.160 16.420 43.360 ;
        RECT 25.820 42.940 35.185 43.360 ;
        RECT 44.495 43.160 65.380 43.360 ;
        RECT 74.735 42.940 78.865 43.360 ;
        RECT 83.375 43.160 93.265 43.360 ;
        RECT 94.895 42.940 95.185 43.360 ;
        RECT 102.575 43.160 122.020 43.360 ;
        RECT 131.375 43.160 141.265 43.360 ;
        RECT 220.655 43.160 230.545 43.360 ;
        RECT 232.175 43.160 239.665 43.360 ;
        RECT 240.815 42.940 244.900 43.360 ;
        RECT 259.055 43.160 269.380 43.360 ;
        RECT 277.775 43.160 287.665 43.360 ;
        RECT 288.815 42.940 292.945 43.360 ;
        RECT 147.740 43.160 165.745 43.360 ;
        RECT 184.655 43.160 194.065 43.360 ;
        RECT 293.660 43.160 315.025 43.360 ;
        RECT 6.575 43.360 15.985 43.580 ;
        RECT 18.095 42.940 20.785 43.580 ;
        RECT 37.295 42.940 39.985 43.580 ;
        RECT 61.775 43.360 65.380 43.580 ;
        RECT 66.095 42.940 68.785 43.580 ;
        RECT 75.215 43.360 78.865 43.580 ;
        RECT 94.940 43.360 95.185 43.580 ;
        RECT 95.855 43.160 98.980 43.580 ;
        RECT 123.695 42.940 126.385 43.580 ;
        RECT 142.940 42.940 145.585 43.580 ;
        RECT 147.740 43.360 156.145 43.580 ;
        RECT 164.495 43.360 165.745 43.580 ;
        RECT 174.575 42.940 177.265 43.580 ;
        RECT 184.655 43.360 187.825 43.580 ;
        RECT 193.295 43.360 194.065 43.580 ;
        RECT 204.335 42.940 206.545 43.580 ;
        RECT 212.975 42.940 215.665 43.580 ;
        RECT 232.175 43.360 235.300 43.580 ;
        RECT 241.295 43.360 244.900 43.580 ;
        RECT 251.375 42.940 254.065 43.580 ;
        RECT 270.575 42.940 273.265 43.580 ;
        RECT 289.295 43.360 292.945 43.580 ;
        RECT 293.660 43.360 293.860 43.580 ;
        RECT 309.455 43.360 315.025 43.580 ;
        RECT 6.095 43.580 15.985 43.780 ;
        RECT 36.815 43.580 40.945 43.780 ;
        RECT 75.215 43.580 79.345 43.780 ;
        RECT 123.215 43.580 127.345 43.780 ;
        RECT 132.815 43.360 136.945 43.780 ;
        RECT 142.940 43.580 156.145 43.780 ;
        RECT 183.695 43.580 187.825 43.780 ;
        RECT 193.295 43.580 197.425 43.780 ;
        RECT 202.895 43.580 207.025 43.780 ;
        RECT 212.495 43.580 216.625 43.780 ;
        RECT 222.095 43.360 226.225 43.780 ;
        RECT 250.895 43.580 255.025 43.780 ;
        RECT 270.095 43.580 274.225 43.780 ;
        RECT 309.455 43.580 315.505 43.780 ;
        RECT 61.775 43.580 69.745 43.780 ;
        RECT 94.940 43.580 98.980 43.780 ;
        RECT 109.775 43.360 121.585 43.780 ;
        RECT 231.695 43.580 235.300 43.780 ;
        RECT 241.295 43.580 250.225 43.780 ;
        RECT 260.495 43.360 269.380 43.780 ;
        RECT 15.215 43.780 15.985 44.000 ;
        RECT 17.665 43.580 21.745 44.000 ;
        RECT 25.820 43.360 26.020 44.000 ;
        RECT 36.815 43.780 39.505 44.000 ;
        RECT 46.415 43.360 50.545 44.000 ;
        RECT 56.015 43.360 60.145 44.000 ;
        RECT 61.775 43.780 62.980 44.000 ;
        RECT 64.175 43.780 69.745 44.000 ;
        RECT 75.215 43.780 76.945 44.000 ;
        RECT 84.815 43.360 92.785 44.000 ;
        RECT 94.940 43.780 98.065 44.000 ;
        RECT 104.015 43.360 108.145 44.000 ;
        RECT 109.775 43.780 118.180 44.000 ;
        RECT 120.815 43.780 121.585 44.000 ;
        RECT 123.215 43.780 125.905 44.000 ;
        RECT 142.940 43.780 143.185 44.000 ;
        RECT 159.740 43.360 163.345 44.000 ;
        RECT 164.495 43.580 168.625 44.000 ;
        RECT 174.095 43.580 178.225 44.000 ;
        RECT 183.695 43.780 185.425 44.000 ;
        RECT 193.295 43.780 195.985 44.000 ;
        RECT 212.495 43.780 215.185 44.000 ;
        RECT 231.695 43.780 233.905 44.000 ;
        RECT 234.575 43.780 235.300 44.000 ;
        RECT 241.295 43.780 245.860 44.000 ;
        RECT 248.495 43.780 250.225 44.000 ;
        RECT 250.895 43.780 253.585 44.000 ;
        RECT 260.495 43.780 265.585 44.000 ;
        RECT 267.695 43.780 269.380 44.000 ;
        RECT 270.095 43.780 272.785 44.000 ;
        RECT 281.135 43.360 283.300 44.000 ;
        RECT 289.295 43.580 293.860 44.000 ;
        RECT 298.895 43.360 303.025 44.000 ;
        RECT 309.455 43.780 309.700 44.000 ;
        RECT 9.455 43.780 11.665 44.200 ;
        RECT 15.215 44.000 26.020 44.200 ;
        RECT 34.415 44.000 39.505 44.200 ;
        RECT 42.095 44.000 62.980 44.200 ;
        RECT 64.175 44.000 76.945 44.200 ;
        RECT 82.895 44.000 98.065 44.200 ;
        RECT 102.095 44.000 118.180 44.200 ;
        RECT 120.815 44.000 125.905 44.200 ;
        RECT 140.015 44.000 143.185 44.200 ;
        RECT 144.380 43.780 145.105 44.200 ;
        RECT 159.215 44.000 170.065 44.200 ;
        RECT 171.695 44.000 185.425 44.200 ;
        RECT 190.895 44.000 195.985 44.200 ;
        RECT 203.375 43.780 206.065 44.200 ;
        RECT 210.095 44.000 215.185 44.200 ;
        RECT 222.575 43.780 222.865 44.200 ;
        RECT 223.535 43.780 225.745 44.200 ;
        RECT 229.295 44.000 233.905 44.200 ;
        RECT 234.575 44.000 245.860 44.200 ;
        RECT 255.215 44.000 265.585 44.200 ;
        RECT 279.695 44.000 309.700 44.200 ;
        RECT 62.780 44.200 62.980 44.420 ;
        RECT 98.780 43.780 98.980 44.420 ;
        RECT 102.095 44.200 117.265 44.420 ;
        RECT 122.255 44.200 125.905 44.420 ;
        RECT 142.460 44.200 143.185 44.420 ;
        RECT 144.380 44.200 144.580 44.420 ;
        RECT 151.580 43.780 153.265 44.420 ;
        RECT 222.620 44.200 222.865 44.420 ;
        RECT 223.535 44.200 225.265 44.420 ;
        RECT 245.615 44.200 245.860 44.420 ;
        RECT 248.495 44.000 253.585 44.420 ;
        RECT 258.575 44.200 265.585 44.420 ;
        RECT 267.695 44.000 272.785 44.420 ;
        RECT 15.695 44.200 20.740 44.620 ;
        RECT 55.055 44.200 60.625 44.620 ;
        RECT 62.780 44.420 63.460 44.620 ;
        RECT 67.535 44.200 70.225 44.620 ;
        RECT 98.780 44.420 117.265 44.620 ;
        RECT 122.255 44.420 126.865 44.620 ;
        RECT 151.535 44.420 155.665 44.620 ;
        RECT 175.535 44.200 177.220 44.620 ;
        RECT 192.335 44.200 195.505 44.620 ;
        RECT 236.975 44.200 244.945 44.620 ;
        RECT 245.615 44.420 254.545 44.620 ;
        RECT 258.575 44.420 274.705 44.620 ;
        RECT 280.655 44.200 294.340 44.620 ;
        RECT 63.260 44.620 63.460 44.840 ;
        RECT 64.700 44.200 64.900 44.840 ;
        RECT 142.460 44.420 144.580 44.840 ;
        RECT 193.775 44.620 195.505 44.840 ;
        RECT 222.620 44.420 225.265 44.840 ;
        RECT 258.575 44.620 261.745 44.840 ;
        RECT 63.260 44.840 64.900 45.040 ;
        RECT 142.415 44.840 144.625 45.040 ;
        RECT 193.775 44.840 196.465 45.040 ;
        RECT 203.855 44.840 232.945 45.040 ;
        RECT 241.775 44.620 244.465 45.040 ;
        RECT 256.175 44.840 261.745 45.040 ;
        RECT 3.215 47.360 306.385 47.560 ;
        RECT 4.220 47.560 13.105 47.980 ;
        RECT 4.220 47.980 4.420 48.200 ;
        RECT 2.000 48.200 4.420 48.400 ;
        RECT 3.695 48.400 4.420 48.620 ;
        RECT 3.695 48.620 10.225 48.820 ;
        RECT 80.975 50.300 88.945 50.500 ;
        RECT 100.655 50.300 108.145 50.500 ;
        RECT 143.855 50.300 147.985 50.500 ;
        RECT 304.655 50.300 312.625 50.500 ;
        RECT 149.615 50.300 239.140 50.500 ;
        RECT 277.295 50.300 287.140 50.500 ;
        RECT 82.415 50.500 88.945 50.720 ;
        RECT 90.575 50.300 98.545 50.720 ;
        RECT 100.655 50.500 100.900 50.720 ;
        RECT 143.855 50.500 146.545 50.720 ;
        RECT 149.615 50.500 156.145 50.720 ;
        RECT 238.895 50.500 239.140 50.720 ;
        RECT 247.055 50.300 255.025 50.720 ;
        RECT 256.655 50.300 264.625 50.720 ;
        RECT 266.255 50.300 274.225 50.720 ;
        RECT 277.295 50.500 277.540 50.720 ;
        RECT 286.895 50.500 287.140 50.720 ;
        RECT 295.055 50.300 303.025 50.720 ;
        RECT 304.655 50.500 306.385 50.720 ;
        RECT 148.175 50.720 156.145 50.920 ;
        RECT 160.655 50.500 168.625 50.920 ;
        RECT 170.255 50.500 178.225 50.920 ;
        RECT 179.855 50.500 187.825 50.920 ;
        RECT 189.935 50.500 197.425 50.920 ;
        RECT 199.055 50.500 207.025 50.920 ;
        RECT 208.655 50.500 216.625 50.920 ;
        RECT 218.255 50.500 226.225 50.920 ;
        RECT 228.335 50.500 235.825 50.920 ;
        RECT 283.535 50.500 283.825 50.920 ;
        RECT 286.895 50.720 306.385 50.920 ;
        RECT 82.415 50.720 100.900 50.920 ;
        RECT 238.895 50.720 277.540 50.920 ;
        RECT 63.695 50.720 69.745 51.140 ;
        RECT 71.375 50.720 79.345 51.140 ;
        RECT 82.415 50.920 82.660 51.140 ;
        RECT 100.700 50.920 100.900 51.140 ;
        RECT 109.775 50.720 117.745 51.140 ;
        RECT 119.855 50.720 127.345 51.140 ;
        RECT 128.975 50.720 136.945 51.140 ;
        RECT 138.575 50.720 146.545 51.140 ;
        RECT 148.175 50.920 149.905 51.140 ;
        RECT 238.895 50.920 245.425 51.140 ;
        RECT 276.335 50.920 277.540 51.140 ;
        RECT 283.535 50.920 283.780 51.140 ;
        RECT 286.895 50.920 293.425 51.140 ;
        RECT 63.215 51.140 82.660 51.340 ;
        RECT 100.700 51.140 149.905 51.340 ;
        RECT 211.535 50.920 216.145 51.340 ;
        RECT 237.455 51.140 245.425 51.340 ;
        RECT 276.335 51.140 283.780 51.340 ;
        RECT 284.495 51.140 293.425 51.340 ;
        RECT 58.895 54.920 311.665 55.120 ;
        RECT 58.895 55.120 59.140 55.340 ;
        RECT 3.215 55.340 59.140 55.540 ;
        RECT 119.855 57.860 123.505 58.060 ;
        RECT 122.735 58.060 123.505 58.280 ;
        RECT 285.935 57.860 289.585 58.280 ;
        RECT 277.295 58.280 306.385 58.480 ;
        RECT 17.135 58.280 21.745 58.700 ;
        RECT 36.335 58.280 40.945 58.700 ;
        RECT 45.935 58.280 50.545 58.700 ;
        RECT 65.135 58.280 69.745 58.700 ;
        RECT 84.335 58.280 88.945 58.700 ;
        RECT 94.415 58.280 98.545 58.700 ;
        RECT 103.535 58.280 108.145 58.700 ;
        RECT 122.735 58.280 127.345 58.700 ;
        RECT 132.335 58.280 136.945 58.700 ;
        RECT 141.935 58.280 146.545 58.700 ;
        RECT 150.575 58.280 163.345 58.700 ;
        RECT 164.015 58.280 168.625 58.700 ;
        RECT 173.615 58.280 178.225 58.700 ;
        RECT 183.215 58.280 187.825 58.700 ;
        RECT 192.815 58.280 198.385 58.700 ;
        RECT 212.015 58.280 216.625 58.700 ;
        RECT 231.215 58.280 235.825 58.700 ;
        RECT 240.815 58.280 245.425 58.700 ;
        RECT 250.415 58.280 255.025 58.700 ;
        RECT 260.015 58.280 264.625 58.700 ;
        RECT 269.615 58.280 274.225 58.700 ;
        RECT 277.295 58.480 277.540 58.700 ;
        RECT 3.215 58.700 277.540 58.900 ;
        RECT 59.855 58.900 61.585 59.320 ;
        RECT 95.375 58.900 143.665 59.320 ;
        RECT 48.380 58.900 58.660 59.320 ;
        RECT 48.380 59.320 48.625 59.540 ;
        RECT 58.415 59.320 58.660 59.540 ;
        RECT 59.855 59.320 61.540 59.540 ;
        RECT 129.455 59.320 133.105 59.740 ;
        RECT 139.055 59.320 142.705 59.740 ;
        RECT 237.935 59.540 241.585 59.740 ;
        RECT 247.535 59.540 251.185 59.740 ;
        RECT 309.455 59.540 315.505 59.740 ;
        RECT 23.855 59.540 27.505 59.960 ;
        RECT 37.340 59.540 48.625 59.960 ;
        RECT 58.415 59.540 61.540 59.960 ;
        RECT 62.255 59.540 65.905 59.960 ;
        RECT 100.655 59.320 104.305 59.960 ;
        RECT 107.855 59.320 109.585 59.960 ;
        RECT 110.255 59.320 112.945 59.960 ;
        RECT 119.855 59.320 121.585 59.960 ;
        RECT 148.655 59.540 152.305 59.960 ;
        RECT 161.135 59.540 164.785 59.960 ;
        RECT 180.335 59.540 183.985 59.960 ;
        RECT 189.935 59.540 193.585 59.960 ;
        RECT 199.535 59.540 203.185 59.960 ;
        RECT 218.735 59.540 222.385 59.960 ;
        RECT 239.855 59.740 241.585 59.960 ;
        RECT 248.975 59.740 251.185 59.960 ;
        RECT 252.335 59.540 259.300 59.960 ;
        RECT 279.215 59.540 283.825 59.960 ;
        RECT 298.415 59.540 303.025 59.960 ;
        RECT 305.135 59.540 308.785 59.960 ;
        RECT 309.455 59.740 310.225 59.960 ;
        RECT 9.455 59.960 124.945 60.160 ;
        RECT 143.855 59.960 237.700 60.160 ;
        RECT 248.975 59.960 310.225 60.160 ;
        RECT 235.275 60.160 237.700 60.380 ;
        RECT 239.855 59.960 244.945 60.380 ;
        RECT 248.975 60.160 256.465 60.380 ;
        RECT 4.655 60.380 8.305 60.580 ;
        RECT 163.055 60.160 182.545 60.580 ;
        RECT 283.055 60.160 309.745 60.580 ;
        RECT 6.095 60.580 8.305 60.800 ;
        RECT 10.475 60.160 12.405 60.800 ;
        RECT 30.575 60.160 45.265 60.800 ;
        RECT 54.575 60.160 54.865 60.800 ;
        RECT 55.435 60.160 57.365 60.800 ;
        RECT 87.215 60.160 89.425 60.800 ;
        RECT 94.895 60.160 97.585 60.800 ;
        RECT 100.395 60.160 102.325 60.800 ;
        RECT 145.355 60.160 147.285 60.800 ;
        RECT 190.315 60.160 192.245 60.800 ;
        RECT 194.735 60.160 198.385 60.800 ;
        RECT 210.140 60.160 230.545 60.800 ;
        RECT 235.275 60.380 256.465 60.800 ;
        RECT 258.620 60.160 258.820 60.800 ;
        RECT 280.235 60.160 282.165 60.800 ;
        RECT 283.055 60.580 297.700 60.800 ;
        RECT 308.975 60.580 309.745 60.800 ;
        RECT 6.095 60.800 103.345 61.000 ;
        RECT 308.975 60.800 311.665 61.000 ;
        RECT 188.015 60.800 297.700 61.000 ;
        RECT 100.655 61.000 103.345 61.220 ;
        RECT 121.775 60.800 150.865 61.220 ;
        RECT 184.175 60.800 186.865 61.220 ;
        RECT 188.015 61.000 210.820 61.220 ;
        RECT 268.655 61.000 297.700 61.220 ;
        RECT 6.575 61.000 24.580 61.420 ;
        RECT 25.775 61.000 31.345 61.420 ;
        RECT 45.455 61.000 50.545 61.420 ;
        RECT 52.655 61.000 56.305 61.420 ;
        RECT 62.255 61.000 63.985 61.420 ;
        RECT 258.140 61.000 265.060 61.420 ;
        RECT 32.060 61.000 38.065 61.420 ;
        RECT 65.180 61.000 92.740 61.420 ;
        RECT 100.655 61.220 210.820 61.420 ;
        RECT 230.255 61.000 240.100 61.420 ;
        RECT 268.655 61.220 307.345 61.420 ;
        RECT 24.380 61.420 24.580 61.640 ;
        RECT 25.775 61.420 30.865 61.640 ;
        RECT 34.415 61.420 38.065 61.640 ;
        RECT 54.095 61.420 56.305 61.640 ;
        RECT 92.495 61.420 92.740 61.640 ;
        RECT 100.655 61.420 103.300 61.640 ;
        RECT 210.095 61.420 210.820 61.640 ;
        RECT 230.255 61.420 234.385 61.640 ;
        RECT 239.855 61.420 240.100 61.640 ;
        RECT 251.855 61.000 253.060 61.640 ;
        RECT 268.655 61.420 272.785 61.640 ;
        RECT 296.975 61.420 307.345 61.640 ;
        RECT 8.495 61.420 11.185 61.840 ;
        RECT 14.255 61.420 14.545 61.840 ;
        RECT 24.380 61.640 30.865 61.840 ;
        RECT 33.455 61.420 33.745 61.840 ;
        RECT 43.055 61.640 43.345 61.840 ;
        RECT 71.855 61.420 75.505 61.840 ;
        RECT 81.455 61.420 81.745 61.840 ;
        RECT 91.055 61.420 91.345 61.840 ;
        RECT 92.495 61.640 103.300 61.840 ;
        RECT 114.095 61.420 116.785 61.840 ;
        RECT 124.655 61.420 127.300 61.840 ;
        RECT 133.295 61.420 135.985 61.840 ;
        RECT 140.015 61.420 145.105 61.840 ;
        RECT 152.495 61.420 155.185 61.840 ;
        RECT 162.095 61.420 162.385 61.840 ;
        RECT 164.975 61.420 167.665 61.840 ;
        RECT 170.735 61.420 171.025 61.840 ;
        RECT 182.255 61.420 195.985 61.840 ;
        RECT 203.375 61.420 206.065 61.840 ;
        RECT 209.135 61.420 209.425 61.840 ;
        RECT 222.575 61.640 225.265 61.840 ;
        RECT 228.335 61.640 228.625 61.840 ;
        RECT 257.135 61.640 257.425 61.840 ;
        RECT 266.735 61.640 267.025 61.840 ;
        RECT 276.335 61.420 276.625 61.840 ;
        RECT 289.775 61.420 292.465 61.840 ;
        RECT 295.535 61.420 295.825 61.840 ;
        RECT 296.975 61.640 316.465 61.840 ;
        RECT 54.095 61.640 60.580 61.840 ;
        RECT 239.855 61.640 253.585 61.840 ;
        RECT 8.495 61.840 10.705 62.060 ;
        RECT 14.300 61.840 14.545 62.060 ;
        RECT 15.215 61.420 20.305 62.060 ;
        RECT 33.500 61.840 33.745 62.060 ;
        RECT 34.415 61.640 39.505 62.060 ;
        RECT 43.100 61.840 43.345 62.060 ;
        RECT 46.895 61.420 49.585 62.060 ;
        RECT 54.095 61.840 59.665 62.060 ;
        RECT 60.380 61.840 60.580 62.060 ;
        RECT 65.180 61.420 65.380 62.060 ;
        RECT 66.095 61.420 68.785 62.060 ;
        RECT 72.815 61.840 75.505 62.060 ;
        RECT 81.500 61.840 81.745 62.060 ;
        RECT 85.295 61.420 87.985 62.060 ;
        RECT 92.495 61.840 97.105 62.060 ;
        RECT 104.495 61.420 107.185 62.060 ;
        RECT 114.095 61.840 116.305 62.060 ;
        RECT 133.295 61.840 135.505 62.060 ;
        RECT 142.415 61.840 145.105 62.060 ;
        RECT 152.495 61.840 154.705 62.060 ;
        RECT 162.140 61.840 162.385 62.060 ;
        RECT 164.975 61.840 167.185 62.060 ;
        RECT 170.780 61.840 171.025 62.060 ;
        RECT 171.695 61.420 176.785 62.060 ;
        RECT 182.255 61.840 186.385 62.060 ;
        RECT 203.375 61.840 205.585 62.060 ;
        RECT 209.180 61.840 209.425 62.060 ;
        RECT 210.095 61.640 215.185 62.060 ;
        RECT 222.575 61.840 224.785 62.060 ;
        RECT 228.380 61.840 228.625 62.060 ;
        RECT 229.295 61.640 234.385 62.060 ;
        RECT 239.855 61.840 243.985 62.060 ;
        RECT 250.895 61.840 253.585 62.060 ;
        RECT 257.180 61.840 257.425 62.060 ;
        RECT 260.975 61.420 263.665 62.060 ;
        RECT 264.860 61.420 265.060 62.060 ;
        RECT 266.780 61.840 267.025 62.060 ;
        RECT 267.695 61.640 272.785 62.060 ;
        RECT 276.380 61.840 276.625 62.060 ;
        RECT 277.340 61.420 278.545 62.060 ;
        RECT 289.775 61.840 291.985 62.060 ;
        RECT 295.580 61.840 295.825 62.060 ;
        RECT 296.975 61.840 303.025 62.060 ;
        RECT 5.615 62.060 10.705 62.260 ;
        RECT 14.300 62.060 21.745 62.260 ;
        RECT 33.500 62.060 40.945 62.260 ;
        RECT 43.100 62.060 50.545 62.260 ;
        RECT 81.500 62.060 88.945 62.260 ;
        RECT 99.695 61.840 101.425 62.260 ;
        RECT 123.215 62.060 123.505 62.260 ;
        RECT 142.415 62.060 146.545 62.260 ;
        RECT 149.615 62.060 154.705 62.260 ;
        RECT 162.140 62.060 167.185 62.260 ;
        RECT 170.780 62.060 178.225 62.260 ;
        RECT 181.295 62.060 186.385 62.260 ;
        RECT 190.460 61.840 192.145 62.260 ;
        RECT 193.295 61.840 195.505 62.260 ;
        RECT 200.495 62.060 205.585 62.260 ;
        RECT 209.180 62.060 216.625 62.260 ;
        RECT 219.695 62.060 224.785 62.260 ;
        RECT 228.380 62.060 235.825 62.260 ;
        RECT 238.895 62.060 243.985 62.260 ;
        RECT 248.060 61.840 249.745 62.260 ;
        RECT 250.895 62.060 255.025 62.260 ;
        RECT 266.780 62.060 274.225 62.260 ;
        RECT 276.380 62.060 283.825 62.260 ;
        RECT 286.895 62.060 291.985 62.260 ;
        RECT 295.580 62.060 303.025 62.260 ;
        RECT 306.095 61.840 311.185 62.260 ;
        RECT 24.380 61.840 29.905 62.260 ;
        RECT 53.615 62.060 59.665 62.260 ;
        RECT 125.135 61.840 127.300 62.260 ;
        RECT 257.180 62.060 265.060 62.260 ;
        RECT 8.015 62.260 10.705 62.480 ;
        RECT 27.215 62.260 29.905 62.480 ;
        RECT 44.975 62.260 50.545 62.480 ;
        RECT 53.615 62.260 54.865 62.480 ;
        RECT 55.535 62.260 59.665 62.480 ;
        RECT 60.380 62.060 69.745 62.480 ;
        RECT 72.815 62.060 77.905 62.480 ;
        RECT 81.500 62.260 86.065 62.480 ;
        RECT 91.100 61.840 91.300 62.480 ;
        RECT 92.015 62.060 97.105 62.480 ;
        RECT 104.015 62.060 109.105 62.480 ;
        RECT 111.215 62.060 116.305 62.480 ;
        RECT 123.260 62.260 123.505 62.480 ;
        RECT 125.135 62.260 126.385 62.480 ;
        RECT 127.100 62.260 127.300 62.480 ;
        RECT 130.415 62.060 135.505 62.480 ;
        RECT 152.015 62.260 154.705 62.480 ;
        RECT 164.495 62.260 167.185 62.480 ;
        RECT 183.695 62.260 186.385 62.480 ;
        RECT 193.775 62.260 195.505 62.480 ;
        RECT 202.895 62.260 205.585 62.480 ;
        RECT 222.095 62.260 224.785 62.480 ;
        RECT 241.295 62.260 243.985 62.480 ;
        RECT 257.180 62.260 259.345 62.480 ;
        RECT 264.860 62.260 265.060 62.480 ;
        RECT 266.780 62.260 269.380 62.480 ;
        RECT 288.815 62.260 291.985 62.480 ;
        RECT 308.015 62.260 311.185 62.480 ;
        RECT 8.015 62.480 12.145 62.680 ;
        RECT 44.975 62.480 54.865 62.680 ;
        RECT 55.535 62.480 86.065 62.680 ;
        RECT 91.100 62.480 98.545 62.680 ;
        RECT 102.575 62.480 122.065 62.680 ;
        RECT 251.375 62.260 254.065 62.680 ;
        RECT 256.175 62.480 259.345 62.680 ;
        RECT 297.935 62.260 298.225 62.680 ;
        RECT 308.015 62.480 312.145 62.680 ;
        RECT 127.100 62.480 136.945 62.680 ;
        RECT 278.300 62.260 283.345 62.680 ;
        RECT 8.975 62.680 12.145 62.900 ;
        RECT 18.095 62.260 20.785 62.900 ;
        RECT 24.380 62.260 26.065 62.900 ;
        RECT 27.215 62.480 31.345 62.900 ;
        RECT 32.060 61.420 32.260 62.900 ;
        RECT 37.295 62.260 39.985 62.900 ;
        RECT 85.820 62.680 86.065 62.900 ;
        RECT 91.100 62.680 95.665 62.900 ;
        RECT 123.260 62.480 126.385 62.900 ;
        RECT 127.100 62.680 127.345 62.900 ;
        RECT 132.380 62.680 136.945 62.900 ;
        RECT 142.895 62.260 145.585 62.900 ;
        RECT 152.015 62.480 156.145 62.900 ;
        RECT 164.495 62.480 168.625 62.900 ;
        RECT 174.575 62.260 177.265 62.900 ;
        RECT 183.695 62.480 187.825 62.900 ;
        RECT 193.775 62.480 196.465 62.900 ;
        RECT 202.895 62.480 207.025 62.900 ;
        RECT 212.975 62.260 215.665 62.900 ;
        RECT 222.095 62.480 226.225 62.900 ;
        RECT 232.175 62.260 234.865 62.900 ;
        RECT 241.295 62.480 245.425 62.900 ;
        RECT 251.375 62.680 252.145 62.900 ;
        RECT 259.100 62.680 259.345 62.900 ;
        RECT 264.860 62.480 269.380 62.900 ;
        RECT 270.575 62.260 273.265 62.900 ;
        RECT 278.300 62.680 278.500 62.900 ;
        RECT 281.135 62.680 283.345 62.900 ;
        RECT 288.815 62.480 292.945 62.900 ;
        RECT 297.980 62.680 298.225 62.900 ;
        RECT 299.375 62.260 302.065 62.900 ;
        RECT 308.495 62.680 312.145 62.900 ;
        RECT 8.975 62.900 40.465 63.100 ;
        RECT 56.015 62.680 61.585 63.100 ;
        RECT 75.215 62.680 79.345 63.100 ;
        RECT 85.820 62.900 95.665 63.100 ;
        RECT 112.655 62.680 117.745 63.100 ;
        RECT 123.260 62.900 127.345 63.100 ;
        RECT 132.380 62.900 252.145 63.100 ;
        RECT 259.100 62.900 278.500 63.100 ;
        RECT 281.135 62.900 293.425 63.100 ;
        RECT 297.980 62.900 302.545 63.100 ;
        RECT 308.495 62.900 312.625 63.100 ;
        RECT 277.295 63.100 278.500 63.320 ;
        RECT 281.135 63.100 282.385 63.320 ;
        RECT 75.695 63.100 78.385 63.520 ;
        RECT 143.375 63.100 144.580 63.520 ;
        RECT 176.015 63.100 178.705 63.520 ;
        RECT 220.700 63.100 227.140 63.520 ;
        RECT 277.295 63.320 282.385 63.520 ;
        RECT 288.860 63.100 291.025 63.520 ;
        RECT 3.215 65.840 306.385 66.040 ;
        RECT 2.255 69.200 13.585 69.400 ;
        RECT 62.255 69.200 69.745 69.400 ;
        RECT 208.175 69.200 216.145 69.400 ;
        RECT 3.215 69.400 13.585 69.620 ;
        RECT 51.695 69.200 60.625 69.620 ;
        RECT 62.255 69.400 63.460 69.620 ;
        RECT 208.175 69.400 210.385 69.620 ;
        RECT 3.215 69.620 63.460 69.820 ;
        RECT 256.655 69.620 264.625 69.820 ;
        RECT 285.935 69.620 293.425 69.820 ;
        RECT 162.095 69.620 210.385 69.820 ;
        RECT 275.855 69.620 283.780 69.820 ;
        RECT 63.215 69.820 63.460 70.040 ;
        RECT 80.975 69.620 88.945 70.040 ;
        RECT 162.095 69.820 168.625 70.040 ;
        RECT 208.655 69.820 210.385 70.040 ;
        RECT 258.095 69.820 264.625 70.040 ;
        RECT 266.255 69.620 274.225 70.040 ;
        RECT 275.855 69.820 277.540 70.040 ;
        RECT 283.535 69.820 283.780 70.040 ;
        RECT 286.895 69.820 293.425 70.040 ;
        RECT 4.175 69.820 12.145 70.240 ;
        RECT 13.775 69.820 21.745 70.240 ;
        RECT 23.375 69.820 31.345 70.240 ;
        RECT 32.975 69.820 40.945 70.240 ;
        RECT 42.575 69.820 50.545 70.240 ;
        RECT 52.175 69.820 60.145 70.240 ;
        RECT 63.215 70.040 100.900 70.240 ;
        RECT 161.135 70.040 168.625 70.240 ;
        RECT 170.255 69.820 178.225 70.240 ;
        RECT 179.855 69.820 187.825 70.240 ;
        RECT 188.975 69.820 197.425 70.240 ;
        RECT 199.055 69.820 207.025 70.240 ;
        RECT 208.655 70.040 216.625 70.240 ;
        RECT 258.095 70.040 277.540 70.240 ;
        RECT 286.895 70.040 306.385 70.240 ;
        RECT 100.700 70.240 100.900 70.460 ;
        RECT 103.055 70.040 108.145 70.460 ;
        RECT 109.775 70.040 117.745 70.460 ;
        RECT 121.295 70.040 127.345 70.460 ;
        RECT 128.975 70.040 136.945 70.460 ;
        RECT 138.575 70.040 146.545 70.460 ;
        RECT 148.175 70.040 156.145 70.460 ;
        RECT 161.135 70.240 162.385 70.460 ;
        RECT 210.095 70.240 216.625 70.460 ;
        RECT 218.255 70.040 226.225 70.460 ;
        RECT 227.855 70.040 235.825 70.460 ;
        RECT 237.455 70.040 245.425 70.460 ;
        RECT 247.055 70.040 255.025 70.460 ;
        RECT 258.095 70.240 258.340 70.460 ;
        RECT 277.295 70.240 277.540 70.460 ;
        RECT 283.535 70.040 283.825 70.460 ;
        RECT 286.895 70.240 287.140 70.460 ;
        RECT 304.655 70.240 306.385 70.460 ;
        RECT 71.375 70.240 79.345 70.660 ;
        RECT 90.575 70.240 98.545 70.660 ;
        RECT 100.700 70.460 162.385 70.660 ;
        RECT 210.095 70.460 258.340 70.660 ;
        RECT 277.295 70.460 287.140 70.660 ;
        RECT 295.055 70.240 303.025 70.660 ;
        RECT 304.655 70.460 312.625 70.660 ;
        RECT 3.215 72.980 59.140 73.180 ;
        RECT 58.895 73.180 59.140 73.400 ;
        RECT 58.895 73.400 311.665 73.600 ;
        RECT 161.135 78.440 165.745 78.640 ;
        RECT 141.455 75.500 144.580 75.700 ;
        RECT 145.355 75.500 147.285 75.700 ;
        RECT 144.380 75.700 144.580 75.920 ;
        RECT 145.355 75.700 146.500 75.920 ;
        RECT 144.380 75.920 146.500 76.540 ;
        RECT 146.255 76.540 146.500 76.760 ;
        RECT 146.255 76.760 146.545 77.180 ;
        RECT 233.135 76.760 234.865 77.180 ;
        RECT 3.215 77.180 306.340 77.380 ;
        RECT 306.095 77.380 306.340 77.600 ;
        RECT 19.055 77.380 21.745 77.800 ;
        RECT 28.655 77.380 31.345 77.800 ;
        RECT 38.255 77.380 40.945 77.800 ;
        RECT 67.055 77.380 69.745 77.800 ;
        RECT 86.255 77.380 88.945 77.800 ;
        RECT 105.455 77.380 108.145 77.800 ;
        RECT 124.655 77.380 127.345 77.800 ;
        RECT 143.855 77.380 146.545 77.800 ;
        RECT 160.175 77.380 160.465 77.800 ;
        RECT 175.535 77.380 178.225 77.800 ;
        RECT 190.895 77.380 191.185 77.800 ;
        RECT 194.735 77.380 197.425 77.800 ;
        RECT 204.335 77.380 207.025 77.800 ;
        RECT 213.935 77.380 216.625 77.800 ;
        RECT 243.215 77.380 245.425 77.800 ;
        RECT 252.335 77.380 255.025 77.800 ;
        RECT 261.935 77.380 264.625 77.800 ;
        RECT 271.535 77.380 274.225 77.800 ;
        RECT 281.135 77.380 283.825 77.800 ;
        RECT 300.335 77.380 303.025 77.800 ;
        RECT 306.095 77.600 306.385 77.800 ;
        RECT 4.655 78.440 8.305 78.640 ;
        RECT 7.055 78.640 8.305 78.860 ;
        RECT 7.055 78.860 12.145 79.280 ;
        RECT 1.775 79.280 13.105 79.480 ;
        RECT 18.620 79.280 30.820 79.480 ;
        RECT 8.975 79.480 13.105 79.700 ;
        RECT 16.095 79.280 18.025 79.700 ;
        RECT 18.620 79.480 18.820 79.700 ;
        RECT 25.775 79.480 30.820 79.700 ;
        RECT 34.940 79.280 56.305 79.700 ;
        RECT 61.055 79.280 62.985 79.700 ;
        RECT 100.655 79.280 103.345 79.700 ;
        RECT 106.015 79.280 107.945 79.700 ;
        RECT 119.855 79.280 121.585 79.700 ;
        RECT 150.975 79.280 152.905 79.700 ;
        RECT 160.220 77.800 160.420 79.700 ;
        RECT 195.935 79.280 197.865 79.700 ;
        RECT 240.895 79.280 242.825 79.700 ;
        RECT 247.535 79.280 252.095 79.700 ;
        RECT 191.855 79.700 206.020 79.900 ;
        RECT 212.015 79.700 252.100 79.900 ;
        RECT 8.975 79.700 18.820 79.900 ;
        RECT 25.775 79.700 163.345 79.900 ;
        RECT 269.660 79.700 279.505 79.900 ;
        RECT 8.975 79.900 10.705 80.120 ;
        RECT 25.775 79.900 30.340 80.120 ;
        RECT 162.095 79.900 163.345 80.120 ;
        RECT 251.900 79.900 252.100 80.120 ;
        RECT 269.660 79.900 269.905 80.120 ;
        RECT 277.295 79.900 279.505 80.120 ;
        RECT 5.615 80.120 10.705 80.320 ;
        RECT 101.615 79.900 106.705 80.320 ;
        RECT 149.615 79.900 154.705 80.320 ;
        RECT 162.095 80.120 167.185 80.320 ;
        RECT 237.935 79.900 238.225 80.320 ;
        RECT 238.895 79.900 243.985 80.320 ;
        RECT 24.815 80.120 30.340 80.320 ;
        RECT 200.495 79.900 206.020 80.320 ;
        RECT 9.935 80.320 10.705 80.540 ;
        RECT 17.615 79.900 18.820 80.540 ;
        RECT 24.815 80.320 26.980 80.540 ;
        RECT 30.140 80.320 30.340 80.540 ;
        RECT 35.420 79.900 35.620 80.540 ;
        RECT 44.015 79.900 49.105 80.540 ;
        RECT 62.255 79.900 63.985 80.540 ;
        RECT 72.815 79.900 77.905 80.540 ;
        RECT 82.415 79.900 87.505 80.540 ;
        RECT 92.015 79.900 97.105 80.540 ;
        RECT 102.095 80.320 106.705 80.540 ;
        RECT 111.215 79.900 116.305 80.540 ;
        RECT 130.415 79.900 135.505 80.540 ;
        RECT 148.655 79.900 148.945 80.540 ;
        RECT 149.615 80.320 153.265 80.540 ;
        RECT 164.015 80.320 167.185 80.540 ;
        RECT 181.295 80.120 186.385 80.540 ;
        RECT 200.495 80.320 202.660 80.540 ;
        RECT 205.820 80.320 206.020 80.540 ;
        RECT 219.695 79.900 224.785 80.540 ;
        RECT 237.980 80.320 238.225 80.540 ;
        RECT 238.895 80.320 242.545 80.540 ;
        RECT 251.900 80.120 269.905 80.540 ;
        RECT 277.295 80.120 282.385 80.540 ;
        RECT 286.895 80.120 291.985 80.540 ;
        RECT 296.495 80.120 301.585 80.540 ;
        RECT 306.095 80.120 311.185 80.540 ;
        RECT 249.500 80.540 316.465 80.740 ;
        RECT 9.935 80.540 26.980 80.740 ;
        RECT 36.380 80.540 100.900 80.740 ;
        RECT 102.095 80.540 153.265 80.740 ;
        RECT 164.015 80.540 202.660 80.740 ;
        RECT 205.820 80.540 235.300 80.740 ;
        RECT 9.935 80.740 16.465 80.960 ;
        RECT 26.735 80.740 26.980 80.960 ;
        RECT 30.140 80.540 35.665 80.960 ;
        RECT 36.380 80.740 36.625 80.960 ;
        RECT 100.700 80.740 100.900 80.960 ;
        RECT 102.095 80.740 123.025 80.960 ;
        RECT 151.580 80.740 153.265 80.960 ;
        RECT 164.015 80.740 164.260 80.960 ;
        RECT 202.415 80.740 202.660 80.960 ;
        RECT 205.820 80.740 212.305 80.960 ;
        RECT 232.175 80.740 235.300 80.960 ;
        RECT 237.980 80.540 242.545 80.960 ;
        RECT 249.500 80.740 249.745 80.960 ;
        RECT 279.215 80.740 308.305 81.160 ;
        RECT 62.780 80.740 73.540 81.160 ;
        RECT 100.700 80.960 123.025 81.160 ;
        RECT 151.580 80.960 164.260 81.160 ;
        RECT 257.660 80.740 268.420 81.160 ;
        RECT 6.575 80.960 16.465 81.380 ;
        RECT 18.095 80.740 20.785 81.380 ;
        RECT 26.735 80.960 36.625 81.380 ;
        RECT 37.295 80.740 39.985 81.380 ;
        RECT 56.495 80.740 59.185 81.380 ;
        RECT 62.780 81.160 68.305 81.380 ;
        RECT 73.295 81.160 73.540 81.380 ;
        RECT 100.700 81.160 102.385 81.380 ;
        RECT 122.780 81.160 123.025 81.380 ;
        RECT 123.695 80.740 126.385 81.380 ;
        RECT 142.895 80.740 145.585 81.380 ;
        RECT 148.220 80.740 150.385 81.380 ;
        RECT 151.580 81.160 151.825 81.380 ;
        RECT 162.620 81.160 164.260 81.380 ;
        RECT 174.575 80.740 177.265 81.380 ;
        RECT 182.255 80.740 192.145 81.380 ;
        RECT 193.775 80.740 196.465 81.380 ;
        RECT 202.415 80.960 212.305 81.380 ;
        RECT 212.975 80.740 215.665 81.380 ;
        RECT 232.175 80.960 249.745 81.380 ;
        RECT 251.375 80.740 254.065 81.380 ;
        RECT 257.660 81.160 263.185 81.380 ;
        RECT 268.175 81.160 268.420 81.380 ;
        RECT 270.575 80.740 273.265 81.380 ;
        RECT 279.695 81.160 308.305 81.380 ;
        RECT 6.095 81.380 68.305 81.580 ;
        RECT 73.295 81.380 102.385 81.580 ;
        RECT 162.620 81.380 263.185 81.580 ;
        RECT 268.175 81.380 278.065 81.580 ;
        RECT 279.695 81.380 308.785 81.580 ;
        RECT 122.780 81.380 151.825 81.580 ;
        RECT 122.780 81.580 125.905 81.800 ;
        RECT 150.095 81.580 151.825 81.800 ;
        RECT 162.620 81.580 162.865 81.800 ;
        RECT 268.175 81.580 272.785 81.800 ;
        RECT 15.215 81.580 20.305 82.000 ;
        RECT 34.415 81.580 39.505 82.000 ;
        RECT 53.615 81.580 58.705 82.000 ;
        RECT 287.375 81.580 297.265 82.000 ;
        RECT 16.175 82.000 20.305 82.220 ;
        RECT 56.015 82.000 58.705 82.220 ;
        RECT 120.815 81.800 125.905 82.220 ;
        RECT 140.015 81.580 145.105 82.220 ;
        RECT 150.095 81.800 162.865 82.220 ;
        RECT 163.535 81.580 171.025 82.220 ;
        RECT 171.695 81.580 176.785 82.220 ;
        RECT 190.895 81.580 195.985 82.220 ;
        RECT 210.095 81.580 215.185 82.220 ;
        RECT 229.295 81.580 234.385 82.220 ;
        RECT 248.495 81.580 253.585 82.220 ;
        RECT 267.695 81.800 272.785 82.220 ;
        RECT 279.740 81.580 279.940 82.220 ;
        RECT 16.175 82.220 26.065 82.420 ;
        RECT 56.015 82.220 279.940 82.420 ;
        RECT 277.775 82.420 279.940 82.640 ;
        RECT 287.420 82.000 287.620 82.640 ;
        RECT 170.735 82.420 182.545 82.840 ;
        RECT 277.775 82.640 287.620 82.840 ;
        RECT 280.235 82.840 282.165 83.260 ;
        RECT 240.895 49.040 242.825 49.240 ;
        RECT 285.855 49.040 287.785 49.240 ;
        RECT 190.315 45.260 192.245 45.460 ;
        RECT 319.055 50.300 322.225 50.500 ;
        RECT 320.495 50.500 322.225 50.720 ;
        RECT 320.495 50.720 323.185 50.920 ;
        RECT 320.495 50.920 320.740 51.140 ;
        RECT 319.055 51.140 320.740 51.340 ;
        RECT 320.495 51.340 320.740 51.560 ;
        RECT 320.495 51.560 322.705 51.760 ;
        RECT 190.315 52.820 192.245 53.020 ;
        RECT 235.275 52.820 237.205 53.020 ;
        RECT 280.235 52.820 282.165 53.020 ;
        RECT 325.195 52.820 327.125 53.020 ;
        RECT 320.015 53.660 322.705 53.860 ;
        RECT 316.655 54.920 320.785 55.120 ;
        RECT 280.235 45.260 282.165 45.460 ;
        RECT 230.735 55.760 234.865 55.960 ;
        RECT 195.935 56.600 197.865 56.800 ;
        RECT 240.895 56.600 242.825 56.800 ;
        RECT 285.855 56.600 287.785 56.800 ;
        RECT 309.935 58.280 315.505 58.480 ;
        RECT 325.195 60.380 327.125 60.580 ;
        RECT 318.095 58.280 321.220 58.480 ;
        RECT 319.100 58.480 319.825 59.120 ;
        RECT 320.495 58.480 321.220 59.120 ;
        RECT 319.100 59.120 321.220 59.740 ;
        RECT 321.020 59.740 321.220 59.960 ;
        RECT 319.100 59.740 319.825 60.160 ;
        RECT 321.020 59.960 323.185 60.160 ;
        RECT 320.975 60.800 321.265 61.000 ;
        RECT 319.100 60.160 319.300 61.220 ;
        RECT 319.100 61.220 319.825 61.640 ;
        RECT 321.020 61.000 321.220 61.640 ;
        RECT 319.055 61.640 321.220 61.840 ;
        RECT 325.195 45.260 327.125 45.460 ;
        RECT 195.935 64.160 197.865 64.360 ;
        RECT 240.895 64.160 242.825 64.360 ;
        RECT 285.855 64.160 287.785 64.360 ;
        RECT 318.095 63.740 320.305 63.940 ;
        RECT 318.575 63.940 320.305 64.160 ;
        RECT 318.575 64.160 320.785 64.360 ;
        RECT 235.275 45.260 237.205 45.680 ;
        RECT 232.655 45.680 242.545 45.880 ;
        RECT 190.315 67.940 192.245 68.140 ;
        RECT 235.275 67.940 237.205 68.140 ;
        RECT 325.195 67.940 327.125 68.140 ;
        RECT 280.235 67.940 282.165 68.360 ;
        RECT 278.735 68.360 284.305 68.560 ;
        RECT 226.895 69.200 234.385 69.400 ;
        RECT 246.575 69.200 254.545 69.400 ;
        RECT 307.055 47.780 315.505 47.980 ;
        RECT 320.975 69.200 321.265 69.400 ;
        RECT 321.020 69.400 321.220 71.300 ;
        RECT 320.975 71.300 321.265 71.500 ;
        RECT 195.935 71.720 197.865 71.920 ;
        RECT 240.895 71.720 242.825 71.920 ;
        RECT 285.855 71.720 287.785 71.920 ;
        RECT 322.415 47.360 322.705 47.560 ;
        RECT 322.415 47.560 322.660 47.780 ;
        RECT 319.055 47.780 322.660 47.980 ;
        RECT 321.455 47.980 322.660 48.200 ;
        RECT 321.455 48.200 323.185 48.400 ;
        RECT 316.655 73.400 320.785 73.600 ;
        RECT 190.315 75.500 192.245 75.700 ;
        RECT 235.275 75.500 237.205 75.700 ;
        RECT 280.235 75.500 282.165 75.700 ;
        RECT 308.015 75.500 315.505 75.700 ;
        RECT 325.195 75.500 327.125 75.700 ;
        RECT 319.535 44.420 326.545 44.620 ;
        RECT 170.735 78.440 175.345 78.640 ;
        RECT 180.335 78.440 184.945 78.640 ;
        RECT 199.535 78.440 204.145 78.640 ;
        RECT 209.135 78.440 213.745 78.640 ;
        RECT 218.735 78.440 223.345 78.640 ;
        RECT 233.135 78.020 235.825 78.220 ;
        RECT 228.335 78.440 232.945 78.640 ;
        RECT 257.135 78.440 261.745 78.640 ;
        RECT 266.735 78.440 271.345 78.640 ;
        RECT 276.335 78.440 280.945 78.640 ;
        RECT 285.935 78.440 290.545 78.640 ;
        RECT 295.535 78.440 300.145 78.640 ;
        RECT 308.495 78.020 315.505 78.220 ;
        RECT 308.495 78.220 309.745 78.440 ;
        RECT 305.135 78.440 309.745 78.640 ;
        RECT 285.855 79.280 287.785 79.480 ;
        RECT 296.975 79.280 315.985 79.480 ;
        RECT 190.315 83.060 192.245 83.260 ;
        RECT 235.275 83.060 237.205 83.260 ;
        RECT 195.935 49.040 197.865 49.240 ;
        RECT 325.195 83.060 327.125 83.260 ;
        RECT 1.775 50.300 13.105 50.500 ;
        RECT 15.215 50.300 63.505 50.500 ;
        RECT 3.215 50.500 13.105 50.720 ;
        RECT 15.215 50.500 15.460 50.720 ;
        RECT 3.215 50.720 15.460 50.920 ;
        RECT 23.375 50.500 31.345 50.920 ;
        RECT 32.975 50.500 40.945 50.920 ;
        RECT 42.575 50.500 50.545 50.920 ;
        RECT 52.655 50.500 60.145 50.920 ;
        RECT 13.775 50.920 15.460 51.140 ;
        RECT 4.175 50.920 12.145 51.340 ;
        RECT 13.775 51.140 21.745 51.340 ;
        RECT 10.475 45.260 12.405 45.460 ;
        RECT 10.475 52.820 12.405 53.020 ;
        RECT 16.095 71.720 18.025 71.920 ;
        RECT 61.055 71.720 62.985 71.920 ;
        RECT 106.015 71.720 107.945 71.920 ;
        RECT 150.975 71.720 152.905 71.920 ;
        RECT 55.435 52.820 57.365 53.020 ;
        RECT 100.395 52.820 102.325 53.020 ;
        RECT 12.380 56.600 13.200 56.800 ;
        RECT 12.380 56.800 12.580 57.020 ;
        RECT 1.775 57.020 12.580 57.220 ;
        RECT 1.775 57.220 2.500 57.440 ;
        RECT 1.295 57.440 2.500 57.640 ;
        RECT 2.300 57.640 2.500 58.180 ;
        RECT 2.000 58.180 2.500 58.480 ;
        RECT 145.355 52.820 147.285 53.020 ;
        RECT 1.295 61.640 3.505 61.840 ;
        RECT 1.340 71.720 2.065 71.920 ;
        RECT 1.340 71.920 1.540 72.560 ;
        RECT 0.865 72.560 2.500 72.760 ;
        RECT 2.300 72.760 2.500 73.300 ;
        RECT 2.000 73.300 2.500 73.600 ;
        RECT 55.435 75.500 57.365 75.700 ;
        RECT 100.395 75.500 102.325 75.700 ;
        RECT 16.095 49.040 18.025 49.240 ;
        RECT 61.055 49.040 62.985 49.240 ;
        RECT 2.000 63.320 3.985 63.520 ;
        RECT 16.095 64.160 18.025 64.360 ;
        RECT 61.055 64.160 62.985 64.360 ;
        RECT 10.475 75.500 12.405 75.920 ;
        RECT 1.775 75.920 13.105 76.120 ;
        RECT 14.255 78.440 18.865 78.640 ;
        RECT 23.855 78.440 28.465 78.640 ;
        RECT 33.455 78.440 38.065 78.640 ;
        RECT 43.055 78.440 47.665 78.640 ;
        RECT 52.655 78.440 57.265 78.640 ;
        RECT 62.255 78.440 66.865 78.640 ;
        RECT 71.855 78.440 76.465 78.640 ;
        RECT 81.455 78.440 86.065 78.640 ;
        RECT 91.055 78.440 95.665 78.640 ;
        RECT 100.655 78.440 105.265 78.640 ;
        RECT 110.255 78.440 114.865 78.640 ;
        RECT 119.855 78.440 124.465 78.640 ;
        RECT 129.455 78.440 134.065 78.640 ;
        RECT 139.055 78.440 143.665 78.640 ;
        RECT 106.015 64.160 107.945 64.360 ;
        RECT 150.975 64.160 152.905 64.360 ;
        RECT 106.015 49.040 107.945 49.240 ;
        RECT 150.975 49.040 152.905 49.240 ;
        RECT 2.000 53.240 5.425 53.440 ;
        RECT 55.435 45.260 57.365 45.460 ;
        RECT 1.775 65.000 13.105 65.200 ;
        RECT 100.395 45.260 102.325 45.460 ;
        RECT 10.475 67.940 12.405 68.140 ;
        RECT 55.435 67.940 57.365 68.140 ;
        RECT 100.395 67.940 102.325 68.140 ;
        RECT 145.355 67.940 147.285 68.140 ;
        RECT 145.355 45.260 147.285 45.460 ;
        RECT 2.000 78.440 3.985 78.640 ;
        RECT 27.695 44.000 30.385 44.200 ;
        RECT 16.095 56.600 18.025 56.800 ;
        RECT 10.475 83.060 12.405 83.260 ;
        RECT 55.435 83.060 57.365 83.260 ;
        RECT 100.395 83.060 102.325 83.260 ;
        RECT 145.355 83.060 147.285 83.260 ;
        RECT 61.055 56.600 62.985 56.800 ;
        RECT 2.000 68.360 3.025 68.560 ;
        RECT 106.015 56.600 107.945 56.800 ;
        RECT 150.975 56.600 152.905 56.800 ;
        RECT 2.000 83.480 2.545 83.680 ;
        RECT 13.295 20.060 16.945 20.260 ;
        RECT 24.815 25.520 29.905 25.720 ;
        RECT 24.815 25.720 26.065 25.940 ;
        RECT 23.375 25.940 26.065 26.140 ;
        RECT 125.135 4.940 127.345 5.140 ;
        RECT 74.255 27.200 77.905 27.400 ;
        RECT 106.015 26.360 108.625 26.560 ;
        RECT 108.380 26.560 108.580 27.200 ;
        RECT 107.375 27.200 108.580 27.400 ;
        RECT 16.095 3.680 18.025 3.880 ;
        RECT 69.455 2.000 83.185 2.200 ;
        RECT 40.220 2.000 60.145 2.200 ;
        RECT 40.220 2.200 40.465 2.420 ;
        RECT 57.935 2.200 60.145 2.420 ;
        RECT 69.455 2.200 71.665 2.420 ;
        RECT 57.935 2.420 71.665 2.620 ;
        RECT 40.175 2.420 40.465 2.840 ;
        RECT 59.375 2.620 71.665 2.840 ;
        RECT 59.375 2.840 75.505 3.040 ;
        RECT 30.575 2.840 52.465 3.040 ;
        RECT 30.575 3.040 44.785 3.260 ;
        RECT 49.775 3.040 52.465 3.260 ;
        RECT 59.375 3.040 67.825 3.260 ;
        RECT 20.975 3.260 44.785 3.460 ;
        RECT 49.775 3.260 67.825 3.460 ;
        RECT 61.055 3.460 62.985 3.880 ;
        RECT 10.475 30.140 12.405 30.340 ;
        RECT 55.435 30.140 57.365 30.340 ;
        RECT 100.395 30.140 102.325 30.340 ;
        RECT 145.355 30.140 147.285 30.340 ;
        RECT 77.135 3.680 87.025 3.880 ;
        RECT 4.175 31.820 12.145 32.240 ;
        RECT 1.775 32.240 13.585 32.440 ;
        RECT 2.780 32.440 13.585 32.660 ;
        RECT 2.780 32.660 15.505 32.860 ;
        RECT 2.780 32.860 2.980 33.080 ;
        RECT 13.775 32.860 15.505 33.080 ;
        RECT 13.775 33.080 21.745 33.280 ;
        RECT 2.000 33.080 2.980 33.380 ;
        RECT 2.300 33.380 2.980 33.500 ;
        RECT 2.300 33.500 3.025 33.700 ;
        RECT 2.300 33.700 2.500 33.920 ;
        RECT 1.775 33.920 2.500 34.120 ;
        RECT 16.095 33.920 18.025 34.120 ;
        RECT 61.055 33.920 62.985 34.120 ;
        RECT 106.015 33.920 107.945 34.120 ;
        RECT 150.975 33.920 152.905 34.120 ;
        RECT 100.655 3.680 107.945 3.880 ;
        RECT 10.475 37.700 12.405 37.900 ;
        RECT 49.775 37.700 51.025 37.900 ;
        RECT 55.435 37.700 57.365 37.900 ;
        RECT 100.395 37.700 102.325 37.900 ;
        RECT 145.355 37.700 147.285 37.900 ;
        RECT 2.000 38.120 3.025 38.320 ;
        RECT 0.815 40.640 3.025 40.840 ;
        RECT 138.095 3.680 140.785 3.880 ;
        RECT 150.975 3.680 152.905 3.880 ;
        RECT 118.415 4.100 123.505 4.300 ;
        RECT 5.135 6.200 6.865 6.400 ;
        RECT 15.695 6.200 19.345 6.400 ;
        RECT 72.335 6.200 76.945 6.400 ;
        RECT 126.575 2.000 129.265 2.200 ;
        RECT 144.335 2.000 146.065 2.200 ;
        RECT 48.335 6.620 64.945 6.820 ;
        RECT 34.895 6.200 38.545 6.620 ;
        RECT 29.135 6.620 47.665 6.820 ;
        RECT 29.135 6.820 33.265 7.040 ;
        RECT 9.935 7.040 33.265 7.240 ;
        RECT 10.475 7.240 12.405 7.660 ;
        RECT 55.435 7.460 57.365 7.660 ;
        RECT 1.775 4.520 5.905 4.720 ;
        RECT 86.735 4.520 94.705 4.720 ;
        RECT 96.335 4.520 102.385 4.720 ;
        RECT 107.375 4.520 113.905 4.720 ;
        RECT 8.060 4.520 37.105 4.720 ;
        RECT 38.735 4.520 56.305 4.720 ;
        RECT 65.660 4.520 75.505 4.720 ;
        RECT 3.695 4.720 5.905 4.940 ;
        RECT 8.060 4.720 8.305 4.940 ;
        RECT 19.535 4.720 37.105 4.940 ;
        RECT 38.735 4.720 40.945 4.940 ;
        RECT 41.660 4.720 56.305 4.940 ;
        RECT 60.815 4.520 61.105 4.940 ;
        RECT 65.660 4.720 65.905 4.940 ;
        RECT 67.535 4.720 75.505 4.940 ;
        RECT 86.735 4.720 87.505 4.940 ;
        RECT 99.260 4.720 102.385 4.940 ;
        RECT 107.375 4.720 110.065 4.940 ;
        RECT 3.695 4.940 8.305 5.140 ;
        RECT 67.535 4.940 79.345 5.140 ;
        RECT 82.415 4.940 87.505 5.140 ;
        RECT 105.935 4.940 110.065 5.140 ;
        RECT 19.535 4.940 40.945 5.140 ;
        RECT 41.660 4.940 65.905 5.140 ;
        RECT 99.260 4.940 104.305 5.140 ;
        RECT 4.655 5.140 8.305 5.360 ;
        RECT 19.535 5.140 20.785 5.360 ;
        RECT 36.815 5.140 40.945 5.360 ;
        RECT 41.660 5.140 41.905 5.360 ;
        RECT 62.735 5.140 65.905 5.360 ;
        RECT 75.215 5.140 79.345 5.360 ;
        RECT 82.415 5.140 86.545 5.360 ;
        RECT 102.095 5.140 104.305 5.360 ;
        RECT 105.935 5.140 109.105 5.360 ;
        RECT 4.655 5.360 9.745 5.560 ;
        RECT 15.695 5.360 20.785 5.560 ;
        RECT 22.415 5.140 22.860 5.560 ;
        RECT 23.855 5.140 28.945 5.560 ;
        RECT 36.815 5.360 41.905 5.560 ;
        RECT 43.055 5.140 48.145 5.560 ;
        RECT 51.695 5.140 54.865 5.560 ;
        RECT 62.735 5.360 67.345 5.560 ;
        RECT 75.215 5.360 80.305 5.560 ;
        RECT 102.095 5.360 109.105 5.560 ;
        RECT 111.695 5.360 119.185 5.560 ;
        RECT 52.655 5.560 54.865 5.780 ;
        RECT 56.015 5.140 56.305 5.780 ;
        RECT 80.060 5.560 80.305 5.780 ;
        RECT 81.935 5.360 86.545 5.780 ;
        RECT 90.095 5.360 92.785 5.780 ;
        RECT 99.260 5.140 99.460 5.780 ;
        RECT 108.860 5.560 109.105 5.780 ;
        RECT 111.695 5.560 118.705 5.780 ;
        RECT 52.655 5.780 57.745 5.980 ;
        RECT 80.060 5.780 99.505 5.980 ;
        RECT 108.860 5.780 118.705 5.980 ;
        RECT 80.060 5.980 90.865 6.200 ;
        RECT 78.575 6.200 90.865 6.400 ;
        RECT 92.495 5.980 96.145 6.400 ;
        RECT 111.695 5.980 115.345 6.400 ;
        RECT 101.615 5.780 101.905 5.980 ;
        RECT 101.615 5.980 101.860 6.200 ;
        RECT 100.700 6.200 101.860 6.620 ;
        RECT 100.700 6.620 102.865 7.040 ;
        RECT 100.700 7.040 112.945 7.240 ;
        RECT 100.700 7.240 102.325 7.460 ;
        RECT 100.395 7.460 102.325 7.660 ;
        RECT 145.355 7.460 147.285 7.660 ;
        RECT 2.000 7.880 3.025 8.080 ;
        RECT 44.015 8.300 50.065 8.500 ;
        RECT 63.215 8.300 67.825 8.500 ;
        RECT 120.815 8.300 125.905 8.500 ;
        RECT 152.015 2.000 153.745 2.200 ;
        RECT 139.055 8.720 147.505 8.920 ;
        RECT 1.775 10.400 32.785 10.600 ;
        RECT 62.255 10.400 64.465 10.600 ;
        RECT 88.175 2.420 98.545 2.620 ;
        RECT 97.775 2.620 98.545 2.840 ;
        RECT 97.775 2.840 106.225 3.040 ;
        RECT 16.095 11.240 18.025 11.440 ;
        RECT 61.055 11.240 62.985 11.440 ;
        RECT 150.975 11.240 152.905 11.660 ;
        RECT 149.615 11.660 157.585 11.860 ;
        RECT 73.295 11.660 80.785 11.860 ;
        RECT 73.775 11.860 79.825 12.280 ;
        RECT 92.495 12.080 99.025 12.280 ;
        RECT 106.015 11.240 107.945 11.660 ;
        RECT 103.055 11.660 108.625 11.860 ;
        RECT 103.535 11.860 108.625 12.080 ;
        RECT 103.535 12.080 109.585 12.280 ;
        RECT 111.695 12.080 117.265 12.280 ;
        RECT 130.895 12.080 137.425 12.280 ;
        RECT 52.175 13.760 60.145 13.960 ;
        RECT 140.495 13.760 146.545 13.960 ;
        RECT 34.895 14.180 41.425 14.380 ;
        RECT 11.375 2.000 37.105 2.200 ;
        RECT 10.475 15.020 12.405 15.220 ;
        RECT 55.435 15.020 57.365 15.220 ;
        RECT 82.895 15.020 87.025 15.220 ;
        RECT 100.395 15.020 102.325 15.220 ;
        RECT 145.355 15.020 147.285 15.220 ;
        RECT 150.095 15.860 157.105 16.060 ;
        RECT 2.000 2.840 2.545 3.040 ;
        RECT 5.135 16.280 32.305 16.480 ;
        RECT 43.535 16.280 51.025 16.480 ;
        RECT 137.615 18.380 141.265 18.580 ;
        RECT 116.975 3.260 121.585 3.460 ;
        RECT 55.535 18.380 60.625 18.580 ;
        RECT 61.055 18.800 62.985 19.000 ;
        RECT 150.975 18.800 152.905 19.000 ;
        RECT 61.775 19.640 65.425 19.840 ;
        RECT 4.655 21.740 8.305 21.940 ;
        RECT 91.055 21.740 94.705 21.940 ;
        RECT 1.775 22.160 2.980 22.360 ;
        RECT 2.780 22.360 2.980 23.000 ;
        RECT 2.000 23.000 2.980 23.200 ;
        RECT 16.095 26.360 18.025 26.560 ;
        RECT 55.535 26.360 59.665 26.560 ;
        RECT 93.455 26.360 99.505 26.560 ;
        RECT 208.655 14.180 216.625 14.380 ;
        RECT 282.095 6.620 282.820 6.820 ;
        RECT 282.620 6.820 282.820 7.460 ;
        RECT 280.235 7.460 324.580 7.660 ;
        RECT 325.195 7.460 327.125 7.660 ;
        RECT 324.380 7.660 324.580 7.880 ;
        RECT 325.195 7.660 326.500 7.880 ;
        RECT 324.380 7.880 326.500 8.080 ;
        RECT 326.255 8.080 326.500 8.300 ;
        RECT 326.255 8.300 326.545 8.500 ;
        RECT 295.535 40.640 299.185 40.840 ;
        RECT 285.855 41.480 287.785 41.680 ;
        RECT 195.935 18.800 197.865 19.000 ;
        RECT 256.655 18.800 265.105 19.000 ;
        RECT 279.215 18.380 302.065 18.580 ;
        RECT 285.855 18.580 287.785 19.000 ;
        RECT 288.335 18.580 291.025 19.000 ;
        RECT 240.895 18.800 242.825 19.220 ;
        RECT 237.455 19.220 244.945 19.420 ;
        RECT 307.055 10.820 314.065 11.020 ;
        RECT 188.495 19.640 193.105 19.840 ;
        RECT 308.975 19.220 319.780 19.420 ;
        RECT 319.055 19.420 319.780 19.840 ;
        RECT 319.100 19.840 319.780 20.480 ;
        RECT 319.100 20.480 325.105 20.680 ;
        RECT 319.100 20.680 321.265 20.900 ;
        RECT 317.660 20.900 321.265 21.100 ;
        RECT 317.660 21.100 317.905 21.320 ;
        RECT 320.015 21.100 321.265 21.320 ;
        RECT 317.615 21.320 317.905 21.520 ;
        RECT 320.015 21.320 322.705 21.520 ;
        RECT 325.295 9.980 326.545 10.180 ;
        RECT 319.055 8.300 322.705 8.500 ;
        RECT 319.055 8.500 320.305 8.720 ;
        RECT 315.695 8.720 320.305 8.920 ;
        RECT 322.895 8.720 323.185 8.920 ;
        RECT 322.940 8.920 323.140 9.560 ;
        RECT 322.940 9.560 325.105 9.760 ;
        RECT 320.060 8.920 320.260 9.980 ;
        RECT 322.940 9.760 323.620 9.980 ;
        RECT 320.060 9.980 323.620 10.180 ;
        RECT 323.375 10.180 323.620 10.400 ;
        RECT 322.460 10.180 322.660 10.820 ;
        RECT 323.375 10.400 323.665 10.820 ;
        RECT 322.460 10.820 324.625 11.020 ;
        RECT 306.575 5.360 313.585 5.560 ;
        RECT 285.935 21.740 289.585 21.940 ;
        RECT 318.575 22.160 320.785 22.360 ;
        RECT 319.535 22.360 320.785 22.580 ;
        RECT 319.535 22.580 322.225 22.780 ;
        RECT 325.195 22.580 327.125 22.780 ;
        RECT 306.095 8.300 313.105 8.500 ;
        RECT 181.295 24.260 186.385 24.460 ;
        RECT 183.695 24.460 186.385 24.680 ;
        RECT 183.695 24.680 187.825 24.880 ;
        RECT 190.415 14.180 195.505 14.380 ;
        RECT 195.935 11.240 197.865 11.440 ;
        RECT 316.655 11.240 321.265 11.440 ;
        RECT 323.375 13.340 324.625 13.540 ;
        RECT 321.455 11.660 323.185 12.080 ;
        RECT 289.295 12.080 325.540 12.280 ;
        RECT 294.095 12.280 294.385 12.700 ;
        RECT 316.500 12.280 316.945 12.700 ;
        RECT 316.700 12.700 316.945 12.920 ;
        RECT 321.020 12.280 321.700 12.920 ;
        RECT 325.340 12.280 325.540 12.920 ;
        RECT 296.495 12.920 306.385 13.120 ;
        RECT 307.535 12.920 315.505 13.120 ;
        RECT 320.540 12.920 323.185 13.120 ;
        RECT 325.295 12.920 326.545 13.120 ;
        RECT 294.140 12.700 294.340 13.340 ;
        RECT 304.655 13.120 306.385 13.340 ;
        RECT 307.535 13.120 312.625 13.340 ;
        RECT 316.700 12.920 319.345 13.340 ;
        RECT 320.540 13.120 320.785 13.340 ;
        RECT 304.655 13.340 312.625 13.540 ;
        RECT 316.655 13.340 320.785 13.540 ;
        RECT 294.140 13.340 294.820 13.760 ;
        RECT 304.655 13.540 309.265 13.760 ;
        RECT 320.540 13.540 320.785 13.760 ;
        RECT 320.540 13.760 322.225 13.960 ;
        RECT 292.655 13.760 309.265 13.960 ;
        RECT 292.655 13.960 296.785 14.180 ;
        RECT 307.055 13.960 309.265 14.180 ;
        RECT 320.540 13.960 320.785 14.180 ;
        RECT 277.295 14.180 296.785 14.380 ;
        RECT 307.055 14.180 315.505 14.380 ;
        RECT 320.495 14.180 320.785 14.380 ;
        RECT 284.495 14.380 293.425 14.800 ;
        RECT 195.935 26.360 197.865 26.560 ;
        RECT 240.895 26.360 242.825 26.560 ;
        RECT 317.135 26.360 320.785 26.560 ;
        RECT 318.095 24.680 321.265 24.880 ;
        RECT 319.535 24.880 321.265 25.100 ;
        RECT 322.895 24.680 323.185 25.100 ;
        RECT 319.535 25.100 323.665 25.300 ;
        RECT 321.980 25.300 323.620 25.720 ;
        RECT 321.980 25.720 322.180 26.360 ;
        RECT 321.935 26.360 322.225 26.560 ;
        RECT 240.895 11.240 242.825 11.440 ;
        RECT 285.855 11.240 287.785 11.440 ;
        RECT 265.295 27.200 274.705 27.400 ;
        RECT 190.315 7.460 192.245 7.660 ;
        RECT 317.135 28.040 318.865 28.240 ;
        RECT 171.695 11.660 176.305 11.860 ;
        RECT 181.295 11.660 188.305 11.860 ;
        RECT 190.315 15.020 192.245 15.220 ;
        RECT 235.275 15.020 237.205 15.220 ;
        RECT 266.255 15.020 274.225 15.220 ;
        RECT 178.415 30.140 187.345 30.340 ;
        RECT 190.315 30.140 192.245 30.340 ;
        RECT 235.275 30.140 237.205 30.340 ;
        RECT 280.235 30.140 282.165 30.340 ;
        RECT 325.195 30.140 327.125 30.340 ;
        RECT 316.655 32.240 321.265 32.440 ;
        RECT 280.235 15.020 282.165 15.220 ;
        RECT 325.775 14.180 326.065 14.380 ;
        RECT 322.895 14.180 325.105 14.600 ;
        RECT 325.775 14.380 326.020 14.600 ;
        RECT 321.935 14.600 326.020 14.800 ;
        RECT 325.195 14.800 326.020 15.020 ;
        RECT 325.195 15.020 327.125 15.220 ;
        RECT 208.175 15.440 211.345 15.640 ;
        RECT 247.055 15.440 255.025 15.640 ;
        RECT 200.495 11.660 206.545 11.860 ;
        RECT 210.095 11.660 216.145 11.860 ;
        RECT 195.935 33.920 197.865 34.120 ;
        RECT 240.895 33.920 242.825 34.120 ;
        RECT 285.855 33.920 287.785 34.120 ;
        RECT 182.735 34.340 188.785 34.540 ;
        RECT 320.495 34.340 320.785 34.540 ;
        RECT 320.540 34.540 320.785 34.760 ;
        RECT 320.540 34.760 321.840 34.960 ;
        RECT 219.695 11.660 225.745 11.860 ;
        RECT 319.055 35.600 320.785 35.800 ;
        RECT 230.735 36.860 234.385 37.060 ;
        RECT 258.095 11.660 262.705 11.860 ;
        RECT 320.015 15.860 322.705 16.280 ;
        RECT 301.295 16.280 326.545 16.480 ;
        RECT 258.575 17.960 262.705 18.160 ;
        RECT 235.275 7.460 237.205 7.660 ;
        RECT 167.375 6.200 174.385 6.400 ;
        RECT 190.315 37.700 192.245 37.900 ;
        RECT 235.275 37.700 237.205 37.900 ;
        RECT 280.235 37.700 282.165 37.900 ;
        RECT 307.055 37.700 314.545 37.900 ;
        RECT 325.195 37.700 327.125 37.900 ;
        RECT 306.575 6.200 310.705 6.400 ;
        RECT 319.535 6.200 326.545 6.400 ;
        RECT 285.935 40.640 289.585 40.840 ;
  END
END CFGMEM_IHP16
END LIBRARY

